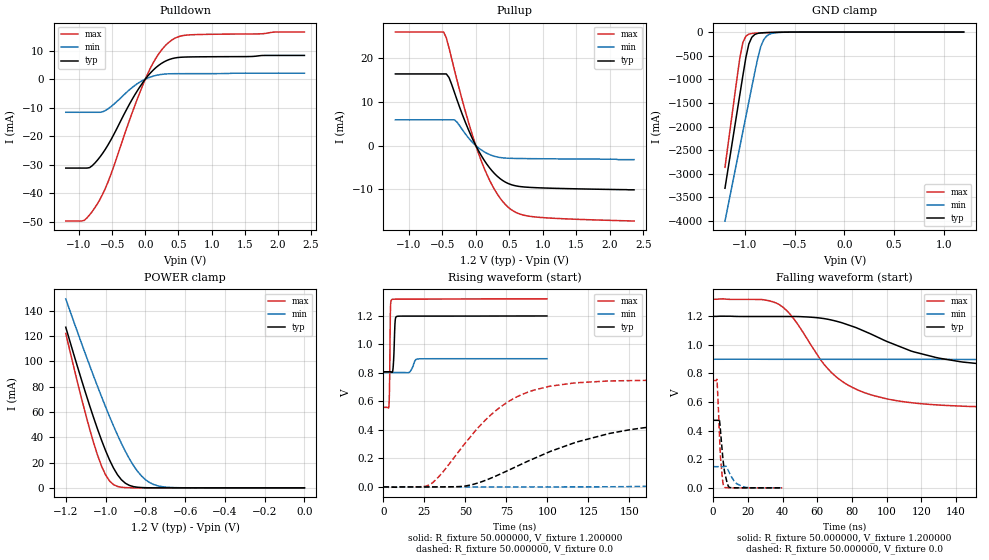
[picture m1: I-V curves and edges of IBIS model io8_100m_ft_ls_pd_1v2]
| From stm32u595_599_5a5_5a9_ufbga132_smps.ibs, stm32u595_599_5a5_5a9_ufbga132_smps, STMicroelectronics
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|   Model io8_100m_ft_ls_pd_1v2
[Model]  io8_100m_ft_ls_pd_1v2
Model_type I/O
Polarity   Non-Inverting
Enable   Active-Low
Vinl =   0.360000V
Vinh =   0.840000V
Vmeas =  0.600000V
Cref =   50.000000pF
Rref =   100.000000M
Vref =   0.0V
C_comp   2.947800pF   2.877700pF   2.996100pF
[Temperature Range]   25.000000   0.140000k   -40.000000
[Pullup Reference]   1.200000V   0.900000V   1.320000V
[Pulldown Reference]   0.0V   0.0V   0.0V
[POWER Clamp Reference]   1.200000V   0.900000V   1.320000V
[GND Clamp Reference]   0.0V   0.0V   0.0V
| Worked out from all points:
|   slope of the pulldown table from 0 to 0.18 V, typ, clamps not added: 40.7 ohm
|   slope of the pullup table from 0 to 0.18 V, typ, clamps not added: 39.5 ohm
|   GND clamp passes 1 mA (typ) near -0.51 V on its own axis
|   POWER clamp passes 1 mA (typ) near -0.86 V on its own axis
|   rising waveform, R_fixture 50.000000, V_fixture 1.200000: 20-80 % time 755ps typ, 2.06ns min, 442ps max; typ from 0.808 V to 1.2 V
|   rising waveform, R_fixture 50.000000, V_fixture 0.0: 20-80 % time 67.2ns typ, 166ns min, 37.1ns max; typ from 0 V to 0.472 V
|   falling waveform, R_fixture 50.000000, V_fixture 1.200000: 20-80 % time 58.2ns typ, 150ns min, 31.6ns max; typ from 1.2 V to 0.808 V
|   falling waveform, R_fixture 50.000000, V_fixture 0.0: 20-80 % time 2.49ns typ, 4.76ns min, 1.84ns max; typ from 0.472 V to 0 V
[Pulldown]
|Voltage   I(typ)   I(min)   I(max)
-1.2V     -31.16mA   -11.61mA   -49.71mA
-920mV    -31.16mA   -11.61mA   -49.48mA
-840mV    -31mA      -11.61mA   -47.54mA
-720mV    -28.33mA   -11.61mA   -43.58mA
-560mV    -22.95mA   -10.37mA   -35.89mA
-200mV    -7.146mA   -2.964mA   -11.89mA
0V        0A         0A         -10fA
160mV     4.047mA    1.298mA    7.361mA
360mV     6.87mA     1.87mA     13mA
480mV     7.543mA    1.91mA     14.69mA
640mV     7.765mA    1.923mA    15.46mA
2.4V      8.308mA    2.101mA    16.51mA
[Pullup]
|Voltage   I(typ)   I(min)   I(max)
-1.2V     16.39mA    5.9mA      25.96mA
-480mV    16.39mA    5.9mA      25.96mA
-440mV    16.39mA    5.9mA      24.63mA
-400mV    15.57mA    5.9mA      22.35mA
-320mV    12.21mA    5.9mA      17.37mA
-120mV    3.997mA    1.962mA    5.905mA
80mV      -2.237mA   -962.6uA   -3.434mA
280mV     -6.404mA   -2.453mA   -10.06mA
520mV     -8.88mA    -2.901mA   -14.54mA
680mV     -9.389mA   -2.951mA   -15.76mA
920mV     -9.627mA   -2.991mA   -16.35mA
2.36V     -10.1mA    -3.2mA     -17.23mA
[GND_clamp]
|Voltage   I(typ)   I(min)   I(max)
-1.2V     -3.305A    -3.998A    -2.862A
-1.05V    -1.316A    -2.418A    -539.3mA
-1.02V    -921mA     -2.103A    -218.8mA
-990mV    -539.5mA   -1.788A    -87.45mA
-960mV    -252.2mA   -1.474A    -44.37mA
-930mV    -110.5mA   -1.16A     -30.33mA
-870mV    -28.04mA   -549.1mA   -21.1mA
-840mV    -18.44mA   -305.6mA   -18.29mA
-810mV    -13.92mA   -159.7mA   -15.75mA
-780mV    -11.24mA   -82.36mA   -13.39mA
-600mV    -2.986mA   -4.279mA   -3.072mA
1.2V      30.28uA    18.17uA    37.27uA
[POWER_clamp]
|Voltage   I(typ)   I(min)   I(max)
-1.2V     127mA      149.4mA    122.2mA
-1.12V    84.97mA    114mA      70.27mA
-1.06V    55.51mA    88.42mA    35.67mA
-1.02V    37.63mA    72.04mA    17.17mA
-1V       29.51mA    64.13mA    10.3mA
-960mV    15.69mA    48.99mA    2.571mA
-900mV    3.624mA    28.77mA    182.8uA
-840mV    490.7uA    13.24mA    11.35uA
-800mV    116.8uA    6.532mA    1.77uA
-740mV    13.2uA     1.723mA    109.1nA
-620mV    167.3nA    79.35uA    0A
0V        0A         17.84nA    0A
[Ramp]
| variable   typ   min   max
dV/dt_r  0.28339/67.10641n   88.78788m/0.16576u  0.45041/37.04761n
dV/dt_f  0.23487/58.11029n   58.03200m/0.14982u  0.45672/31.53662n
R_load = 50.000000
[Rising Waveform]
R_fixture= 50.000000
V_fixture= 1.200000
V_fixture_min= 0.900000
V_fixture_max= 1.320000
|time   V(typ)   V(min)   V(max)
0s        808mV      802.7mV    558.2mV
3.403ns   808mV      802.7mV    574.6mV
3.804ns   808.1mV    802.7mV    764.5mV
4.204ns   808mV      802.7mV    1.211V
5.205ns   803.5mV    802.7mV    1.315V
6.006ns   851.7mV    802.7mV    1.317V
7.207ns   1.172V     802.7mV    1.317V
8.208ns   1.196V     802.7mV    1.317V
21.22ns   1.199V     898mV      1.318V
99.7ns    1.199V     899.4mV    1.319V
[Rising Waveform]
R_fixture= 50.000000
V_fixture= 0.0
V_fixture_min= 0.0
V_fixture_max= 0.0
|time   V(typ)   V(min)   V(max)
0s        2.199nV    207.3nV    1.402nV
28.03ns   -93.5uV    -27.23uV   14mV
50.05ns   6.453mV    -21.99uV   309mV
72.07ns   94.59mV    16.67uV    566.5mV
92.09ns   200.4mV    68.84uV    680.1mV
118.1ns   315.6mV    408.4uV    730.8mV
172.2ns   431.6mV    7.619mV    749.8mV
258.3ns   468.5mV    57.1mV     750.8mV
462.5ns   472.3mV    136.1mV    750.7mV
997ns     472.4mV    148.1mV    750.8mV
[Falling Waveform]
R_fixture= 50.000000
V_fixture= 1.200000
V_fixture_min= 0.900000
V_fixture_max= 1.320000
|time   V(typ)   V(min)   V(max)
0s        1.199V     899.4mV    1.319V
36.04ns   1.198V     899.1mV    1.294V
46.05ns   1.198V     899.1mV    1.189V
64.06ns   1.184V     899.1mV    861.5mV
76.08ns   1.147V     899.1mV    730.9mV
100.1ns   1.024V     899.1mV    622.2mV
132.1ns   903.2mV    898.6mV    577.6mV
172.2ns   845.4mV    895.4mV    562.8mV
278.3ns   811.5mV    849mV      558.1mV
997ns     808mV      802.7mV    558.2mV
[Falling Waveform]
R_fixture= 50.000000
V_fixture= 0.0
V_fixture_min= 0.0
V_fixture_max= 0.0
|time   V(typ)   V(min)   V(max)
0s        472.4mV    148.1mV    750.8mV
2.242ns   472.4mV    148.1mV    755.6mV
3.604ns   479.5mV    148.1mV    395.5mV
4.324ns   393.3mV    148.1mV    211.3mV
5.606ns   215.1mV    147.9mV    43.66mV
6.166ns   150.7mV    148.2mV    8.392mV
8.088ns   36.11mV    138.5mV    820.7uV
9.449ns   2.52mV     103.9mV    223.7uV
17.22ns   14.62uV    8.39mV     -46.01uV
39.88ns   2.199nV    207.3nV    1.402nV
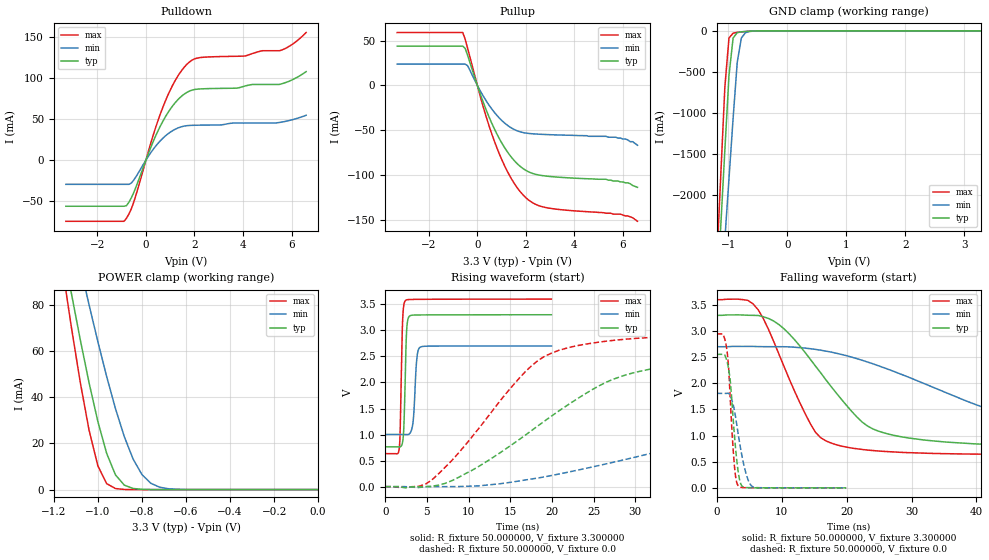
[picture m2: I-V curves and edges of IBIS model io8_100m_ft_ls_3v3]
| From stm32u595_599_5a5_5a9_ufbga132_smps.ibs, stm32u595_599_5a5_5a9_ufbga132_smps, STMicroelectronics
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|   Model io8_100m_ft_ls_3v3
[Model]  io8_100m_ft_ls_3v3
Model_type I/O
Polarity   Non-Inverting
Enable   Active-Low
Vinl =   0.990000V
Vinh =   2.310000V
Vmeas =  1.650000V
Cref =   50.000000pF
Rref =   100.000000M
Vref =   0.0V
C_comp   3.313100pF   3.281800pF   3.354500pF
[Temperature Range]   25.000000   0.140000k   -40.000000
[Pullup Reference]   3.300000V   2.700000V   3.600000V
[Pulldown Reference]   0.0V   0.0V   0.0V
[POWER Clamp Reference]   3.300000V   2.700000V   3.600000V
[GND Clamp Reference]   0.0V   0.0V   0.0V
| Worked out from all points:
|   slope of the pulldown table from 0 to 0.495 V, typ, clamps not added: 14 ohm
|   slope of the pullup table from 0 to 0.495 V, typ, clamps not added: 13.7 ohm
|   GND clamp passes 1 mA (typ) near -0.51 V on its own axis
|   POWER clamp passes 1 mA (typ) near -0.85 V on its own axis
|   rising waveform, R_fixture 50.000000, V_fixture 3.300000: 20-80 % time 251ps typ, 341ps min, 235ps max; typ from 0.764 V to 3.3 V
|   rising waveform, R_fixture 50.000000, V_fixture 0.0: 20-80 % time 14.6ns typ, 31.2ns min, 9.34ns max; typ from 0 V to 2.55 V
|   falling waveform, R_fixture 50.000000, V_fixture 3.300000: 20-80 % time 10ns typ, 23.1ns min, 6.36ns max; typ from 3.3 V to 0.764 V
|   falling waveform, R_fixture 50.000000, V_fixture 0.0: 20-80 % time 1.02ns typ, 1.54ns min, 818ps max; typ from 2.55 V to 0 V
[Pulldown]
|Voltage   I(typ)   I(min)   I(max)
-3.3V     -56.06mA   -29.42mA   -74.35mA
-900mV    -56.06mA   -29.42mA   -74.35mA
-700mV    -51.09mA   -29.42mA   -65.48mA
-500mV    -39.32mA   -24.2mA    -50.88mA
300mV     22.62mA    13.13mA    30.43mA
800mV     52.54mA    29.36mA    71.75mA
1.3V      72.91mA    38.82mA    101.4mA
1.8V      84.02mA    42.13mA    119.4mA
2.2V      86.43mA    42.46mA    124.5mA
5.5V      91.98mA    45.75mA    132.9mA
6.1V      98.6mA     49.6mA     142.1mA
6.6V      107.5mA    54.5mA     155mA
[Pullup]
|Voltage   I(typ)   I(min)   I(max)
-3.3V     43.8mA     23.73mA    58.97mA
-600mV    43.8mA     23.73mA    58.97mA
-500mV    41.28mA    23.73mA    51.53mA
-400mV    33.57mA    21.9mA     41.51mA
300mV     -22.93mA   -14.5mA    -29.27mA
800mV     -54.04mA   -33.36mA   -69.41mA
1.4V      -80.24mA   -47.59mA   -104.2mA
2.1V      -96.56mA   -53.74mA   -127.9mA
3V        -101.9mA   -55.18mA   -137.5mA
5.7V      -107mA     -58mA      -144mA
6.2V      -109mA     -61mA      -146mA
6.6V      -114mA     -67mA      -152mA
[GND_clamp]
|Voltage   I(typ)   I(min)   I(max)
-3.3V     -9.848A    -9.957A    -9.458A
-1.2V     -3.312A    -4.013A    -2.863A
-1.13V    -2.381A    -3.274A    -1.769A
-1.06V    -1.452A    -2.535A    -684.7mA
-990mV    -542.9mA   -1.798A    -88.02mA
-920mV    -87.11mA   -1.064A    -28.44mA
-850mV    -22.1mA    -382.4mA   -19.61mA
-780mV    -11.97mA   -86.98mA   -13.71mA
-710mV    -7.619mA   -22.26mA   -8.745mA
-640mV    -4.493mA   -7.773mA   -4.817mA
-360mV    -31.22uA   -172.6uA   -8.607uA
3.28V     0A         15.66nA    -5.841nA
[POWER_clamp]
|Voltage   I(typ)   I(min)   I(max)
-3.28V    1.355A     1.167A     1.664A
-1.16V    105.7mA    131.6mA    95.69mA
-1.12V    84.97mA    114mA      70.27mA
-1.08V    65.05mA    96.83mA    46.54mA
-1.04V    46.34mA    80.15mA    25.76mA
-1V       29.51mA    64.13mA    10.3mA
-960mV    15.69mA    48.99mA    2.571mA
-920mV    6.373mA    35.1mA     455.6uA
-840mV    490.7uA    13.24mA    11.36uA
-760mV    27.33uA    2.767mA    276.6nA
-640mV    346.6nA    134.1uA    15.62nA
0V        0A         19.91nA    0A
[Ramp]
| variable   typ   min   max
dV/dt_r  1.53252/14.60637n   1.08432/31.19621n   1.76664/9.31314n
dV/dt_f  1.52148/10.00275n   1.01892/23.07140n   1.77963/6.34628n
R_load = 50.000000
[Rising Waveform]
R_fixture= 50.000000
V_fixture= 3.300000
V_fixture_min= 2.700000
V_fixture_max= 3.600000
|time   V(typ)   V(min)   V(max)
0s        764.2mV    1.002V     633.9mV
1.682ns   762.3mV    1.002V     731.5mV
2.082ns   853.1mV    1.002V     3.162V
2.242ns   1.17V      1.002V     3.495V
2.442ns   2.344V     1.001V     3.574V
2.763ns   3.234V     1.002V     3.591V
3.323ns   3.293V     1.218V     3.594V
3.804ns   3.295V     2.474V     3.595V
4.204ns   3.296V     2.678V     3.596V
19.94ns   3.3V       2.7V       3.6V
[Rising Waveform]
R_fixture= 50.000000
V_fixture= 0.0
V_fixture_min= 0.0
V_fixture_max= 0.0
|time   V(typ)   V(min)   V(max)
0s        17.53nV    119.4nV    55.53nV
5.606ns   7.05mV     -448.8uV   129.3mV
11.21ns   387.1mV    14.87mV    1.114V
16.02ns   897.2mV    107.3mV    2.069V
19.22ns   1.271V     190.9mV    2.51V
27.23ns   2.054V     462.9mV    2.806V
34.43ns   2.325V     738.3mV    2.884V
59.26ns   2.523V     1.516V     2.94V
94.49ns   2.552V     1.752V     2.944V
398.8ns   2.554V     1.807V     2.944V
[Falling Waveform]
R_fixture= 50.000000
V_fixture= 3.300000
V_fixture_min= 2.700000
V_fixture_max= 3.600000
|time   V(typ)   V(min)   V(max)
0s        3.3V       2.7V       3.6V
4.805ns   3.302V     2.706V     3.587V
6.406ns   3.297V     2.703V     3.405V
10.41ns   3.038V     2.7V       2.312V
16.02ns   2.202V     2.634V     959.3mV
21.62ns   1.352V     2.471V     747.5mV
25.63ns   1.057V     2.304V     698.7mV
46.45ns   810.2mV    1.363V     640mV
76.08ns   770.8mV    1.088V     634.4mV
398.8ns   764.2mV    1.002V     633.9mV
[Falling Waveform]
R_fixture= 50.000000
V_fixture= 0.0
V_fixture_min= 0.0
V_fixture_max= 0.0
|time   V(typ)   V(min)   V(max)
0s        2.554V     1.807V     2.944V
920.9ps   2.554V     1.807V     2.944V
1.562ns   2.438V     1.808V     2.66V
1.842ns   2.279V     1.81V      2.314V
2.082ns   2.072V     1.763V     1.755V
2.683ns   1.102V     1.521V     512.9mV
3.323ns   311.1mV    1.033V     39.72mV
4.525ns   5.998mV    276.9mV    3.705mV
5.606ns   2.233mV    17.3mV     2.761mV
19.94ns   17.53nV    119.4nV    55.53nV
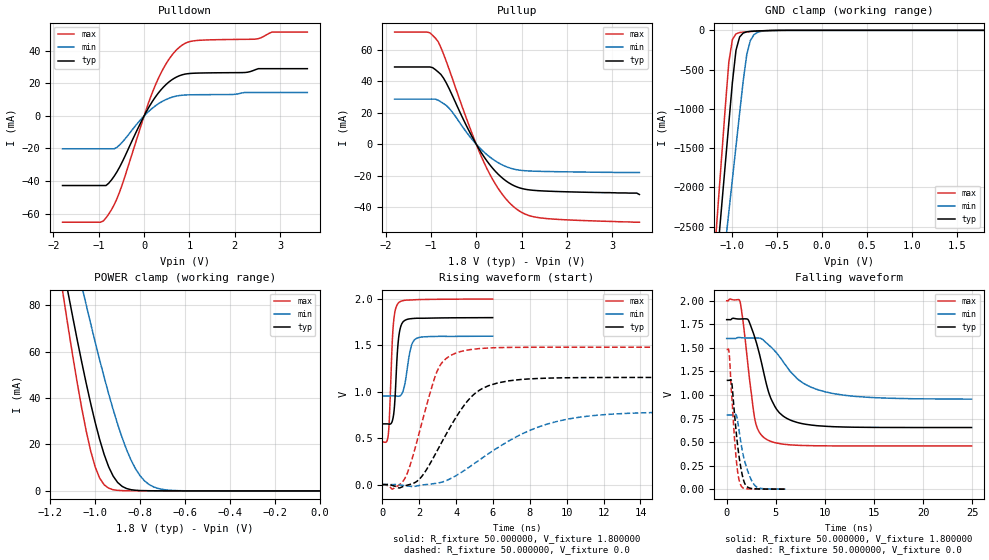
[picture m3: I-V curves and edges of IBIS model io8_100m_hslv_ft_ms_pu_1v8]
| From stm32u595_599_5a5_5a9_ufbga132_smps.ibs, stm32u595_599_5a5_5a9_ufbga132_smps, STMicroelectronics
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|   Model io8_100m_hslv_ft_ms_pu_1v8
[Model]  io8_100m_hslv_ft_ms_pu_1v8
Model_type I/O
Polarity   Non-Inverting
Enable   Active-Low
Vinl =   0.540000V
Vinh =   1.260000V
Vmeas =  0.900000V
Cref =   50.000000pF
Rref =   100.000000M
Vref =   0.0V
C_comp   3.235100pF   3.233200pF   3.282800pF
[Temperature Range]   25.000000   0.140000k   -40.000000
[Pullup Reference]   1.800000V   1.600000V   2.000000V
[Pulldown Reference]   0.0V   0.0V   0.0V
[POWER Clamp Reference]   1.800000V   1.600000V   2.000000V
[GND Clamp Reference]   0.0V   0.0V   0.0V
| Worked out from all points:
|   slope of the pulldown table from 0 to 0.27 V, typ, clamps not added: 21.7 ohm
|   slope of the pullup table from 0 to 0.27 V, typ, clamps not added: 22.6 ohm
|   GND clamp passes 1 mA (typ) near -0.51 V on its own axis
|   POWER clamp passes 1 mA (typ) near -0.86 V on its own axis
|   rising waveform, R_fixture 50.000000, V_fixture 1.800000: 20-80 % time 206ps typ, 322ps min, 192ps max; typ from 0.655 V to 1.8 V
|   rising waveform, R_fixture 50.000000, V_fixture 0.0: 20-80 % time 2.12ns typ, 4.11ns min, 1.26ns max; typ from 0.001 V to 1.16 V
|   falling waveform, R_fixture 50.000000, V_fixture 1.800000: 20-80 % time 1.9ns typ, 3.69ns min, 1.06ns max; typ from 1.8 V to 0.655 V
|   falling waveform, R_fixture 50.000000, V_fixture 0.0: 20-80 % time 745ps typ, 1.02ns min, 591ps max; typ from 1.16 V to 0.001 V
[Pulldown]
|Voltage   I(typ)   I(min)   I(max)
-1.8V     -42.74mA   -20.21mA   -65.25mA
-960mV    -42.74mA   -20.21mA   -65.25mA
-780mV    -41.3mA    -20.21mA   -60.25mA
-540mV    -31.39mA   -17.82mA   -46.65mA
0V        0A         0A         0A
240mV     11.28mA    6.002mA    18.38mA
480mV     19.17mA    10.02mA    31.83mA
780mV     24.67mA    12.5mA     42.21mA
1.14V     26.24mA    12.99mA    46.23mA
2.46V     28.42mA    14.38mA    47.14mA
2.82V     28.99mA    14.38mA    51.44mA
3.6V      28.99mA    14.38mA    51.44mA
[Pullup]
|Voltage   I(typ)   I(min)   I(max)
-1.8V     49.08mA    28.63mA    71.26mA
-1.08V    49.08mA    28.63mA    71.26mA
-840mV    45.94mA    27.95mA    65.24mA
-720mV    41.96mA    25.82mA    57.24mA
-600mV    35.46mA    22.92mA    47.84mA
-180mV    9.685mA    6.268mA    13.58mA
180mV     -8.368mA   -5.234mA   -12.14mA
540mV     -20.62mA   -12.68mA   -30.5mA
900mV     -27.22mA   -16.28mA   -41.49mA
1.14V     -28.94mA   -17mA      -45.14mA
1.5V      -29.77mA   -17.34mA   -47.14mA
3.6V      -32mA      -18mA      -49.6mA
[GND_clamp]
|Voltage   I(typ)   I(min)   I(max)
-1.8V     -9.707A    -9.942A    -9.774A
-1.2V     -3.309A    -4.006A    -2.864A
-1.16V    -2.777A    -3.584A    -2.239A
-1.12V    -2.246A    -3.162A    -1.614A
-1.04V    -1.186A    -2.319A    -408.6mA
-1V       -663.9mA   -1.898A    -117.8mA
-960mV    -254mA     -1.478A    -45.14mA
-920mV    -86.03mA   -1.06A     -28.58mA
-840mV    -19.12mA   -308.9mA   -18.74mA
-800mV    -13.39mA   -130.8mA   -15.31mA
-720mV    -7.948mA   -25.37mA   -9.381mA
1.8V      0A         14.95nA    0A
[POWER_clamp]
|Voltage   I(typ)   I(min)   I(max)
-1.8V     470.9mA    433.7mA    554.6mA
-1.14V    95.28mA    122.7mA    82.88mA
-1.12V    85mA       114mA      70.34mA
-1.06V    55.55mA    88.43mA    35.73mA
-1.04V    46.38mA    80.17mA    25.83mA
-1V       29.54mA    64.14mA    10.37mA
-940mV    10.43mA    41.88mA    1.177mA
-900mV    3.66mA     28.79mA    250.5uA
-840mV    527.2uA    13.26mA    94.87uA
-800mV    153.8uA    6.55mA     88.76uA
-740mV    60.08uA    1.741mA    70.81uA
0V        0A         18.15nA    0A
[Ramp]
| variable   typ   min   max
dV/dt_r  0.69287/2.11680n   0.47199/4.10950n   0.88855/1.25761n
dV/dt_f  0.68716/1.89749n   0.38583/3.69003n   0.92438/1.05316n
R_load = 50.000000
[Rising Waveform]
R_fixture= 50.000000
V_fixture= 1.800000
V_fixture_min= 1.600000
V_fixture_max= 2.000000
|time   V(typ)   V(min)   V(max)
0s        654.8mV    956.1mV    459.4mV
324.3ps   653.5mV    956.2mV    543.8mV
384.4ps   651.6mV    956.3mV    735.2mV
588.6ps   727.3mV    956.3mV    1.707V
684.7ps   925.5mV    955.9mV    1.866V
852.9ps   1.524V     952.6mV    1.953V
1.093ns   1.747V     993.5mV    1.982V
1.562ns   1.789V     1.488V     1.99V
1.826ns   1.793V     1.573V     1.993V
5.982ns   1.8V       1.6V       2V
[Rising Waveform]
R_fixture= 50.000000
V_fixture= 0.0
V_fixture_min= 0.0
V_fixture_max= 0.0
|time   V(typ)   V(min)   V(max)
0s        521.2uV    669.3uV    497.7uV
550.6ps   -9.762mV   627.1uV    -49.01mV
1.201ns   -14.47mV   -10.34mV   60.59mV
2.052ns   68.27mV    -7.349mV   598.4mV
2.953ns   358mV      15mV       1.214V
4.154ns   774.7mV    116.1mV    1.429V
5.756ns   1.066V     332.9mV    1.472V
7.908ns   1.139V     576.7mV    1.48V
10.16ns   1.152V     710mV      1.481V
24.92ns   1.156V     787.5mV    1.481V
[Falling Waveform]
R_fixture= 50.000000
V_fixture= 1.800000
V_fixture_min= 1.600000
V_fixture_max= 2.000000
|time   V(typ)   V(min)   V(max)
0s        1.8V       1.6V       2V
1.351ns   1.807V     1.61V      1.994V
2.152ns   1.803V     1.604V     1.331V
2.853ns   1.613V     1.605V     750.5mV
4.054ns   1.112V     1.552V     529.3mV
4.905ns   878.6mV    1.467V     494.6mV
5.706ns   779.9mV    1.36V      478.5mV
7.257ns   706.5mV    1.166V     466.2mV
10.11ns   667.7mV    1.032V     460.4mV
24.92ns   654.8mV    956.1mV    459.4mV
[Falling Waveform]
R_fixture= 50.000000
V_fixture= 0.0
V_fixture_min= 0.0
V_fixture_max= 0.0
|time   V(typ)   V(min)   V(max)
0s        1.156V     787.5mV    1.481V
240.2ps   1.155V     787.6mV    1.453V
492.5ps   1.145V     787.7mV    1.019V
768.8ps   830.7mV    790.7mV    579.6mV
997ps     575.8mV    781.9mV    292.7mV
1.189ns   402.6mV    674.7mV    135.4mV
1.405ns   250.7mV    521.8mV    50.3mV
1.886ns   51.07mV    278.1mV    5.84mV
2.811ns   4.631mV    46.35mV    1.986mV
5.982ns   521.2uV    669.3uV    497.7uV
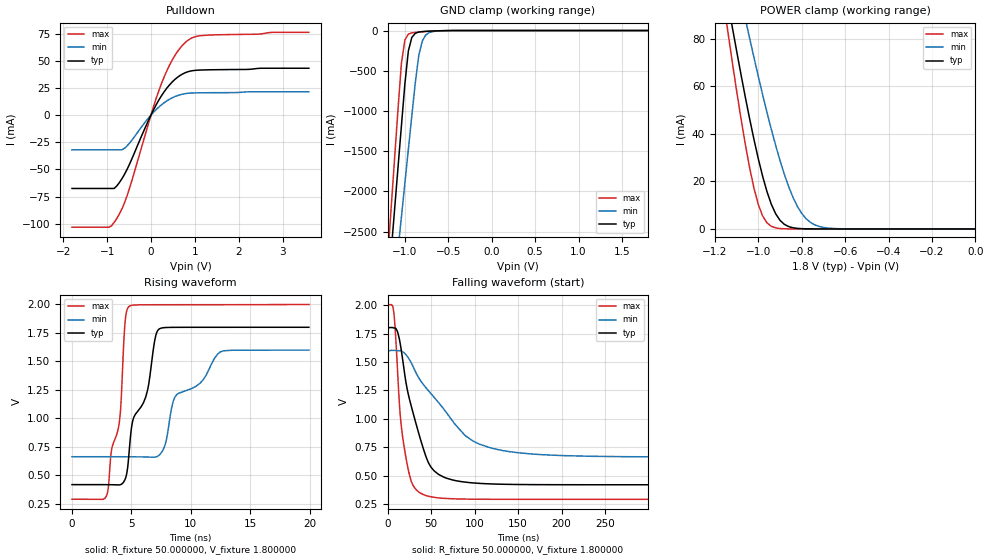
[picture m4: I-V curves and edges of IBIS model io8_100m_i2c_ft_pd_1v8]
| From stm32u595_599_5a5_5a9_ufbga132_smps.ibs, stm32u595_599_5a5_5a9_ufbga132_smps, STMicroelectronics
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|   Model io8_100m_i2c_ft_pd_1v8
[Model]  io8_100m_i2c_ft_pd_1v8
Model_type I/O_open_drain
Polarity   Non-Inverting
Enable   Active-Low
Vinl =   0.540000V
Vinh =   1.260000V
Vmeas =  0.900000V
Cref =   50.000000pF
Rref =   10.000000k
Vref =   1.800000V
C_comp   3.154800pF   3.154000pF   3.203200pF
[Temperature Range]   25.000000   0.140000k   -40.000000
[Pullup Reference]   1.800000V   1.600000V   2.000000V
[Pulldown Reference]   0.0V   0.0V   0.0V
[POWER Clamp Reference]   1.800000V   1.600000V   2.000000V
[GND Clamp Reference]   0.0V   0.0V   0.0V
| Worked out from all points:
|   slope of the pulldown table from 0 to 0.27 V, typ, clamps not added: 13.8 ohm
|   GND clamp passes 1 mA (typ) near -0.51 V on its own axis
|   POWER clamp passes 1 mA (typ) near -0.86 V on its own axis
|   rising waveform, R_fixture 50.000000, V_fixture 1.800000: 20-80 % time 1.94ns typ, 3.43ns min, 1.12ns max; typ from 0.419 V to 1.8 V
|   falling waveform, R_fixture 50.000000, V_fixture 1.800000: 20-80 % time 25.6ns typ, 57.3ns min, 11.9ns max; typ from 1.8 V to 0.419 V
[Pulldown]
|Voltage   I(typ)   I(min)   I(max)
-1.8V     -67.53mA   -31.92mA   -103.2mA
-960mV    -67.53mA   -31.92mA   -103.2mA
-840mV    -67.53mA   -31.92mA   -98.87mA
-780mV    -65.26mA   -31.92mA   -95.24mA
-660mV    -58.47mA   -31.92mA   -86.15mA
-540mV    -49.6mA    -28.16mA   -73.74mA
0V        0A         0A         0A
240mV     17.82mA    9.483mA    29.05mA
540mV     32.64mA    16.95mA    54.49mA
840mV     39.89mA    20.07mA    68.75mA
1.2V      41.57mA    20.56mA    73.35mA
3.6V      43.14mA    21.43mA    76.19mA
[GND_clamp]
|Voltage   I(typ)   I(min)   I(max)
-1.8V     -9.707A    -9.942A    -9.774A
-1.2V     -3.309A    -4.006A    -2.865A
-1.16V    -2.777A    -3.584A    -2.239A
-1.12V    -2.246A    -3.162A    -1.614A
-1.04V    -1.186A    -2.319A    -408.7mA
-1V       -663.9mA   -1.898A    -117.8mA
-960mV    -254mA     -1.478A    -45.15mA
-920mV    -86.04mA   -1.06A     -28.6mA
-840mV    -19.13mA   -308.9mA   -18.75mA
-800mV    -13.4mA    -130.8mA   -15.33mA
-720mV    -7.959mA   -25.38mA   -9.395mA
1.8V      45.71uA    33.33uA    56.11uA
[POWER_clamp]
|Voltage   I(typ)   I(min)   I(max)
-1.8V     470.8mA    433.7mA    554.6mA
-1.14V    95.25mA    122.7mA    82.82mA
-1.12V    84.97mA    114mA      70.27mA
-1.06V    55.51mA    88.42mA    35.67mA
-1.04V    46.34mA    80.15mA    25.76mA
-1V       29.51mA    64.13mA    10.3mA
-940mV    10.39mA    41.86mA    1.109mA
-900mV    3.624mA    28.77mA    182.8uA
-840mV    490.7uA    13.24mA    11.35uA
-800mV    116.8uA    6.532mA    1.77uA
-740mV    13.2uA     1.723mA    109.3nA
0V        0A         18.72nA    0A
[Ramp]
| variable   typ   min   max
dV/dt_r  0.82816/1.94110n   0.56104/3.43302n   1.02518/1.12128n
dV/dt_f  0.82834/25.55606n   0.56138/57.21737n   1.02518/11.91880n
R_load = 50.000000
[Rising Waveform]
R_fixture= 50.000000
V_fixture= 1.800000
V_fixture_min= 1.600000
V_fixture_max= 2.000000
|time   V(typ)   V(min)   V(max)
0s        418.8mV    663.5mV    290.7mV
2.963ns   418.3mV    663.5mV    337.2mV
3.323ns   418mV      663.5mV    719.5mV
4.004ns   416.9mV    663.5mV    982.4mV
4.444ns   459.5mV    663.3mV    1.815V
4.805ns   700.8mV    663mV      1.982V
7.327ns   1.783V     676.4mV    1.997V
8.689ns   1.799V     1.192V     1.997V
12.49ns   1.799V     1.584V     1.997V
19.94ns   1.799V     1.599V     1.999V
[Falling Waveform]
R_fixture= 50.000000
V_fixture= 1.800000
V_fixture_min= 1.600000
V_fixture_max= 2.000000
|time   V(typ)   V(min)   V(max)
0s        1.799V     1.599V     1.999V
7.207ns   1.799V     1.601V     1.939V
14.41ns   1.669V     1.598V     1.051V
20.82ns   1.338V     1.568V     674mV
27.23ns   1.113V     1.492V     449.9mV
38.44ns   805mV      1.33V      342.8mV
58.46ns   511.4mV    1.144V     303.5mV
88.89ns   442.5mV    855.1mV    292.8mV
119.3ns   426.2mV    741.7mV    291mV
398.8ns   418.8mV    663.5mV    290.7mV
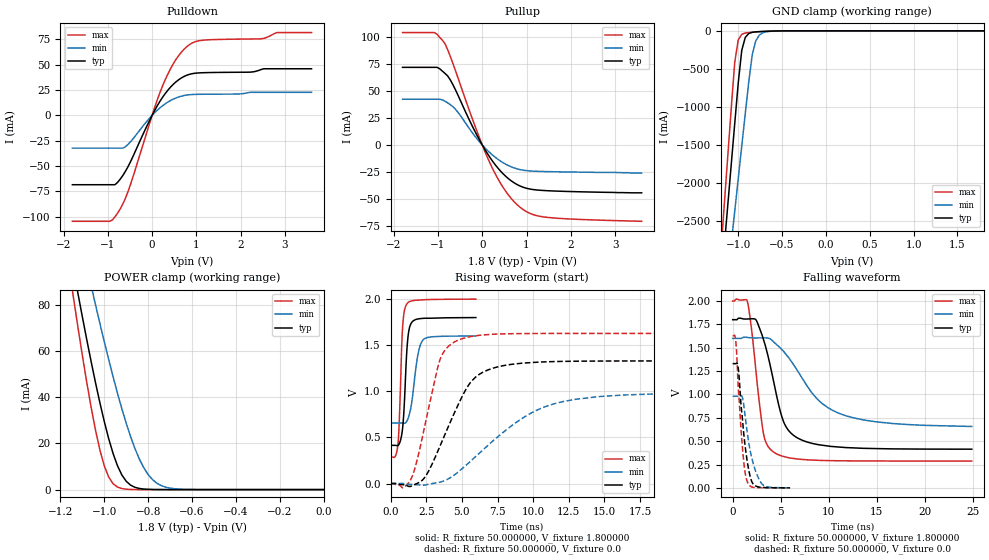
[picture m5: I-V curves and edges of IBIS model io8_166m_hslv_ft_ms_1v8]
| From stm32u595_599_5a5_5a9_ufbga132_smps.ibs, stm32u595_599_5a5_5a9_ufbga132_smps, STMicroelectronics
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|   Model io8_166m_hslv_ft_ms_1v8
[Model]  io8_166m_hslv_ft_ms_1v8
Model_type I/O
Polarity   Non-Inverting
Enable   Active-Low
Vinl =   0.540000V
Vinh =   1.260000V
Vmeas =  0.900000V
Cref =   50.000000pF
Rref =   100.000000M
Vref =   0.0V
C_comp   3.358400pF   3.352800pF   3.400400pF
[Temperature Range]   25.000000   0.140000k   -40.000000
[Pullup Reference]   1.800000V   1.600000V   2.000000V
[Pulldown Reference]   0.0V   0.0V   0.0V
[POWER Clamp Reference]   1.800000V   1.600000V   2.000000V
[GND Clamp Reference]   0.0V   0.0V   0.0V
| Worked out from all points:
|   slope of the pulldown table from 0 to 0.27 V, typ, clamps not added: 13.6 ohm
|   slope of the pullup table from 0 to 0.27 V, typ, clamps not added: 15.9 ohm
|   GND clamp passes 1 mA (typ) near -0.51 V on its own axis
|   POWER clamp passes 1 mA (typ) near -0.86 V on its own axis
|   rising waveform, R_fixture 50.000000, V_fixture 1.800000: 20-80 % time 285ps typ, 490ps min, 232ps max; typ from 0.414 V to 1.8 V
|   rising waveform, R_fixture 50.000000, V_fixture 0.0: 20-80 % time 2.38ns typ, 4.83ns min, 1.41ns max; typ from 0 V to 1.33 V
|   falling waveform, R_fixture 50.000000, V_fixture 1.800000: 20-80 % time 1.98ns typ, 4.45ns min, 1.12ns max; typ from 1.8 V to 0.414 V
|   falling waveform, R_fixture 50.000000, V_fixture 0.0: 20-80 % time 794ps typ, 1.05ns min, 630ps max; typ from 1.33 V to 0 V
[Pulldown]
|Voltage   I(typ)   I(min)   I(max)
-1.8V     -68.38mA   -32.32mA   -104.4mA
-960mV    -68.38mA   -32.32mA   -104.4mA
-780mV    -66.08mA   -32.32mA   -96.42mA
-540mV    -50.22mA   -28.51mA   -74.66mA
0V        0A         -400fA     0A
240mV     18.04mA    9.6mA      29.42mA
480mV     30.68mA    16.02mA    50.95mA
780mV     39.48mA    19.99mA    67.57mA
1.14V     41.99mA    20.78mA    74.01mA
2.46V     45.09mA    22.69mA    75.45mA
2.82V     45.91mA    22.69mA    81.58mA
3.6V      45.91mA    22.69mA    81.58mA
[Pullup]
|Voltage   I(typ)   I(min)   I(max)
-1.8V     71.67mA    42.21mA    103.8mA
-1.08V    71.67mA    42.21mA    103.8mA
-840mV    66.04mA    40.35mA    93.41mA
-720mV    60.01mA    37.18mA    81.6mA
-600mV    50.51mA    32.72mA    68.09mA
-180mV    13.77mA    8.913mA    19.32mA
180mV     -11.9mA    -7.442mA   -17.26mA
480mV     -26.98mA   -16.65mA   -39.76mA
840mV     -37.65mA   -22.63mA   -57.07mA
1.08V     -40.74mA   -24.01mA   -63.22mA
1.44V     -42.19mA   -24.58mA   -66.73mA
3.6V      -44.2mA    -26mA      -70.5mA
[GND_clamp]
|Voltage   I(typ)   I(min)   I(max)
-1.8V     -9.908A    -9.683A    -9.994A
-1.2V     -3.383A    -4.084A    -2.934A
-1.16V    -2.841A    -3.655A    -2.294A
-1.12V    -2.299A    -3.226A    -1.656A
-1.04V    -1.218A    -2.369A    -414.2mA
-1V       -684.7mA   -1.941A    -119.2mA
-960mV    -257.2mA   -1.514A    -45.66mA
-920mV    -87.03mA   -1.089A    -28.93mA
-840mV    -19.35mA   -312.8mA   -18.97mA
-800mV    -13.55mA   -132.4mA   -15.49mA
-720mV    -8.042mA   -25.67mA   -9.491mA
1.8V      0A         13.64nA    0A
[POWER_clamp]
|Voltage   I(typ)   I(min)   I(max)
-1.8V     470.8mA    433.7mA    554.6mA
-1.14V    95.25mA    122.7mA    82.82mA
-1.12V    84.97mA    114mA      70.27mA
-1.06V    55.51mA    88.42mA    35.67mA
-1.04V    46.34mA    80.15mA    25.76mA
-1V       29.51mA    64.13mA    10.3mA
-940mV    10.39mA    41.86mA    1.109mA
-900mV    3.624mA    28.77mA    182.8uA
-840mV    490.7uA    13.24mA    11.35uA
-800mV    116.8uA    6.532mA    1.77uA
-740mV    13.2uA     1.724mA    109.3nA
0V        0A         18.75nA    0A
[Ramp]
| variable   typ   min   max
dV/dt_r  0.79770/2.37724n   0.58715/4.82437n   0.97662/1.40803n
dV/dt_f  0.83153/1.97182n   0.56146/4.43655n   1.02770/1.11781n
R_load = 50.000000
[Rising Waveform]
R_fixture= 50.000000
V_fixture= 1.800000
V_fixture_min= 1.600000
V_fixture_max= 2.000000
|time   V(typ)   V(min)   V(max)
0s        413.9mV    656.9mV    287.2mV
516.5ps   412.3mV    657mV      425mV
612.6ps   432.3mV    657mV      689.1mV
840.8ps   596mV      655.5mV    1.687V
1.105ns   1.345V     667.3mV    1.939V
1.213ns   1.578V     700.3mV    1.961V
1.369ns   1.712V     783.3mV    1.976V
1.886ns   1.784V     1.369V     1.988V
2.246ns   1.791V     1.552V     1.992V
5.982ns   1.8V       1.6V       2V
[Rising Waveform]
R_fixture= 50.000000
V_fixture= 0.0
V_fixture_min= 0.0
V_fixture_max= 0.0
|time   V(typ)   V(min)   V(max)
0s        -16.28uV   -2.041uV   -26.58uV
850.9ps   -12.33mV   244.6uV    -47.07mV
1.451ns   -27.91mV   -9.694mV   54.62mV
2.352ns   57.35mV    -17.03mV   591mV
3.453ns   401.2mV    15.03mV    1.338V
4.705ns   842.9mV    120.4mV    1.553V
5.656ns   1.106V     248.8mV    1.595V
6.757ns   1.227V     403.8mV    1.614V
11.56ns   1.323V     868.6mV    1.628V
24.92ns   1.33V      980.3mV    1.628V
[Falling Waveform]
R_fixture= 50.000000
V_fixture= 1.800000
V_fixture_min= 1.600000
V_fixture_max= 2.000000
|time   V(typ)   V(min)   V(max)
0s        1.8V       1.6V       2V
1.552ns   1.808V     1.61V      1.989V
2.452ns   1.796V     1.605V     1.224V
3.203ns   1.591V     1.606V     587mV
4.304ns   1.122V     1.559V     380mV
5.556ns   655.2mV    1.429V     329.7mV
7.708ns   492.4mV    1.099V     300.5mV
9.96ns    447.7mV    856.3mV    291.9mV
12.56ns   427.9mV    750.5mV    288.6mV
24.92ns   413.9mV    656.9mV    287.2mV
[Falling Waveform]
R_fixture= 50.000000
V_fixture= 0.0
V_fixture_min= 0.0
V_fixture_max= 0.0
|time   V(typ)   V(min)   V(max)
0s        1.33V      980.3mV    1.628V
324.3ps   1.33V      980.4mV    1.568V
420.4ps   1.334V     980.5mV    1.438V
552.6ps   1.302V     980.5mV    1.136V
1.093ns   650.7mV    931mV      345.5mV
1.297ns   449.8mV    773.7mV    163.8mV
1.526ns   281.2mV    590.3mV    66.53mV
2.078ns   50.28mV    284.3mV    7.156mV
3.027ns   5.268mV    46.05mV    1.36mV
5.982ns   -16.28uV   -2.041uV   -26.58uV
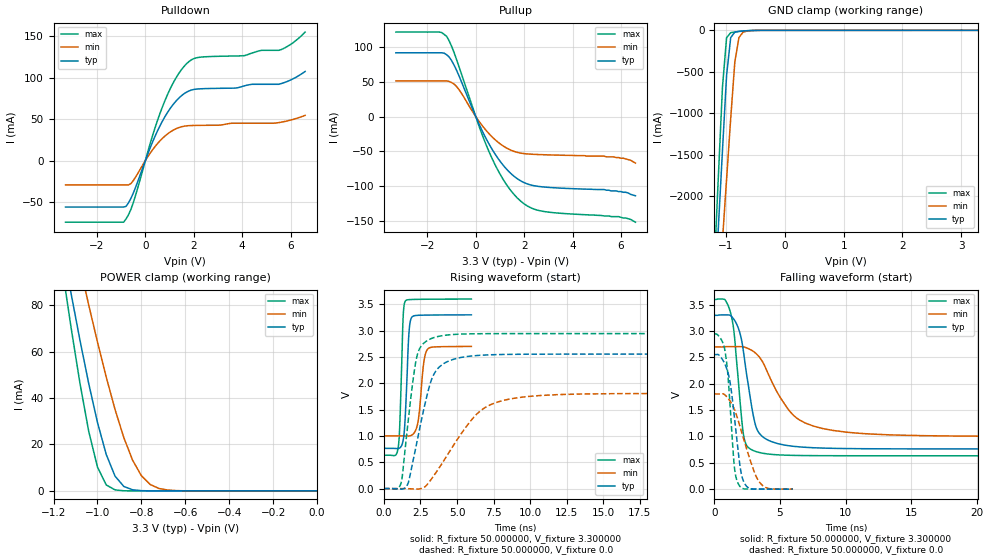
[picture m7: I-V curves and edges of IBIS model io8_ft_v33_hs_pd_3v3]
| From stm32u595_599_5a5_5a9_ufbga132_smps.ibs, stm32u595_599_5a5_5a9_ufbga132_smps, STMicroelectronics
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|   Model io8_ft_v33_hs_pd_3v3
[Model]  io8_ft_v33_hs_pd_3v3
Model_type I/O
Polarity   Non-Inverting
Enable   Active-Low
Vinl =   0.990000V
Vinh =   2.310000V
Vmeas =  1.650000V
Cref =   50.000000pF
Rref =   100.000000M
Vref =   0.0V
C_comp   3.252200pF   3.221000pF   3.293600pF
[Temperature Range]   25.000000   0.140000k   -40.000000
[Pullup Reference]   3.300000V   2.700000V   3.600000V
[Pulldown Reference]   0.0V   0.0V   0.0V
[POWER Clamp Reference]   3.300000V   2.700000V   3.600000V
[GND Clamp Reference]   0.0V   0.0V   0.0V
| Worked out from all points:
|   slope of the pulldown table from 0 to 0.495 V, typ, clamps not added: 14 ohm
|   slope of the pullup table from 0 to 0.495 V, typ, clamps not added: 13.7 ohm
|   GND clamp passes 1 mA (typ) near -0.50 V on its own axis
|   POWER clamp passes 1 mA (typ) near -0.85 V on its own axis
|   rising waveform, R_fixture 50.000000, V_fixture 3.300000: 20-80 % time 237ps typ, 338ps min, 194ps max; typ from 0.764 V to 3.3 V
|   rising waveform, R_fixture 50.000000, V_fixture 0.0: 20-80 % time 1.24ns typ, 2.77ns min, 756ps max; typ from 0 V to 2.55 V
|   falling waveform, R_fixture 50.000000, V_fixture 3.300000: 20-80 % time 973ps typ, 2.53ns min, 636ps max; typ from 3.3 V to 0.764 V
|   falling waveform, R_fixture 50.000000, V_fixture 0.0: 20-80 % time 731ps typ, 1.36ns min, 509ps max; typ from 2.55 V to 0 V
[Pulldown]
|Voltage   I(typ)   I(min)   I(max)
-3.3V     -56.06mA   -29.42mA   -74.35mA
-900mV    -56.06mA   -29.42mA   -74.35mA
-700mV    -51.09mA   -29.42mA   -65.48mA
-500mV    -39.32mA   -24.2mA    -50.88mA
300mV     22.62mA    13.13mA    30.42mA
800mV     52.54mA    29.36mA    71.75mA
1.3V      72.91mA    38.82mA    101.4mA
1.8V      84.02mA    42.13mA    119.4mA
2.2V      86.43mA    42.46mA    124.5mA
5.5V      92.01mA    45.75mA    133mA
6.1V      98.6mA     49.6mA     142.1mA
6.6V      107.5mA    54.5mA     155mA
[Pullup]
|Voltage   I(typ)   I(min)   I(max)
-3.3V     91.69mA    51.24mA    121.4mA
-1.5V     91.69mA    51.24mA    121.4mA
-1.2V     88.75mA    51.24mA    115.3mA
-800mV    67.17mA    43.46mA    82.71mA
100mV     -8.009mA   -5.102mA   -10.2mA
600mV     -42.64mA   -26.6mA    -54.61mA
1.2V      -72.81mA   -43.84mA   -94.18mA
1.9V      -93.37mA   -52.9mA    -122.9mA
2.3V      -98.71mA   -54.23mA   -131.7mA
2.8V      -101.3mA   -54.97mA   -136.5mA
5.7V      -107mA     -58mA      -144mA
6.6V      -114mA     -67mA      -152mA
[GND_clamp]
|Voltage   I(typ)   I(min)   I(max)
-3.3V     -9.848A    -9.957A    -9.458A
-1.2V     -3.312A    -4.013A    -2.863A
-1.13V    -2.381A    -3.274A    -1.769A
-1.06V    -1.452A    -2.535A    -684.8mA
-990mV    -542.9mA   -1.798A    -88.04mA
-920mV    -87.13mA   -1.064A    -28.45mA
-850mV    -22.11mA   -382.4mA   -19.62mA
-780mV    -11.98mA   -86.98mA   -13.73mA
-710mV    -7.63mA    -22.27mA   -8.759mA
-640mV    -4.504mA   -7.781mA   -4.831mA
-360mV    -39.8uA    -178.9uA   -19.56uA
3.28V     83.52uA    56.87uA    102.4uA
[POWER_clamp]
|Voltage   I(typ)   I(min)   I(max)
-3.28V    1.355A     1.167A     1.664A
-1.16V    105.7mA    131.6mA    95.69mA
-1.12V    84.97mA    114mA      70.27mA
-1.08V    65.05mA    96.83mA    46.54mA
-1.04V    46.34mA    80.15mA    25.76mA
-1V       29.51mA    64.13mA    10.3mA
-960mV    15.69mA    48.99mA    2.571mA
-920mV    6.373mA    35.1mA     455.6uA
-840mV    490.7uA    13.24mA    11.36uA
-760mV    27.33uA    2.767mA    276.6nA
-640mV    346.6nA    134.1uA    15.48nA
0V        0A         19.91nA    0A
[Ramp]
| variable   typ   min   max
dV/dt_r  1.53198/1.24162n   1.08384/2.76975n   1.76610/0.75458n
dV/dt_f  1.52117/0.97076n   1.01862/2.52687n   1.77922/0.63338n
R_load = 50.000000
[Rising Waveform]
R_fixture= 50.000000
V_fixture= 3.300000
V_fixture_min= 2.700000
V_fixture_max= 3.600000
|time   V(typ)   V(min)   V(max)
0s        764mV      1.001V     633.8mV
985ps     760.7mV    1.001V     791.4mV
1.093ns   772.9mV    1.001V     1.258V
1.321ns   923.5mV    1.001V     3.28V
1.453ns   1.329V     999.7mV    3.555V
1.706ns   2.919V     998.6mV    3.587V
1.898ns   3.249V     1.014V     3.591V
2.342ns   3.29V      1.282V     3.594V
2.955ns   3.294V     2.635V     3.595V
5.982ns   3.299V     2.699V     3.599V
[Rising Waveform]
R_fixture= 50.000000
V_fixture= 0.0
V_fixture_min= 0.0
V_fixture_max= 0.0
|time   V(typ)   V(min)   V(max)
0s        32.79uV    27.42uV    26.75uV
1.141ns   -10.23mV   82.2uV     77.7mV
1.261ns   -10.23mV   130.3uV    236.3mV
1.622ns   77.98mV    -1.37mV    1.182V
2.282ns   914.8mV    -9.747mV   2.535V
3.363ns   2.14V      225.7mV    2.862V
4.204ns   2.392V     576.9mV    2.912V
6.186ns   2.522V     1.367V     2.939V
8.408ns   2.548V     1.69V      2.943V
29.91ns   2.553V     1.806V     2.943V
[Falling Waveform]
R_fixture= 50.000000
V_fixture= 3.300000
V_fixture_min= 2.700000
V_fixture_max= 3.600000
|time   V(typ)   V(min)   V(max)
0s        3.299V     2.699V     3.599V
1.201ns   3.301V     2.705V     3.383V
1.502ns   3.221V     2.705V     2.993V
1.802ns   3.078V     2.705V     2.156V
2.282ns   2.507V     2.698V     959.8mV
3.003ns   1.361V     2.61V      729.8mV
3.784ns   976.6mV    2.367V     678.4mV
6.006ns   813.7mV    1.406V     641.5mV
8.228ns   780.3mV    1.152V     635.6mV
29.91ns   764mV      1.001V     633.8mV
[Falling Waveform]
R_fixture= 50.000000
V_fixture= 0.0
V_fixture_min= 0.0
V_fixture_max= 0.0
|time   V(typ)   V(min)   V(max)
0s        2.553V     1.806V     2.943V
528.5ps   2.497V     1.808V     2.842V
840.8ps   2.356V     1.783V     2.589V
1.069ns   2.19V      1.719V     2.074V
1.526ns   1.39V      1.519V     443.6mV
1.826ns   714.8mV    1.303V     105.6mV
2.054ns   302.2mV    1.11V      28.97mV
2.354ns   89.89mV    857mV      3.319mV
3.483ns   1.453mV    119.4mV    829.9uV
5.982ns   32.79uV    27.42uV    26.75uV
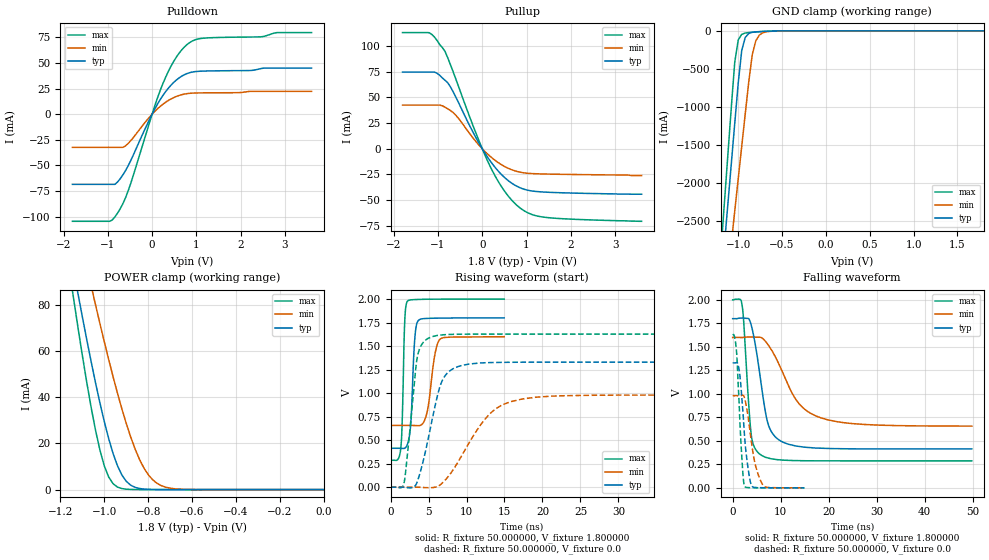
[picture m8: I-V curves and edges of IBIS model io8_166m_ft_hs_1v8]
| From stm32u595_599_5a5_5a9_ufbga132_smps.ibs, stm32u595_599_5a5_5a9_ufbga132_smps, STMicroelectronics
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|   Model io8_166m_ft_hs_1v8
[Model]  io8_166m_ft_hs_1v8
Model_type I/O
Polarity   Non-Inverting
Enable   Active-Low
Vinl =   0.540000V
Vinh =   1.260000V
Vmeas =  0.900000V
Cref =   50.000000pF
Rref =   100.000000M
Vref =   0.0V
C_comp   3.358200pF   3.352700pF   3.400300pF
[Temperature Range]   25.000000   0.140000k   -40.000000
[Pullup Reference]   1.800000V   1.600000V   2.000000V
[Pulldown Reference]   0.0V   0.0V   0.0V
[POWER Clamp Reference]   1.800000V   1.600000V   2.000000V
[GND Clamp Reference]   0.0V   0.0V   0.0V
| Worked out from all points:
|   slope of the pulldown table from 0 to 0.27 V, typ, clamps not added: 13.6 ohm
|   slope of the pullup table from 0 to 0.27 V, typ, clamps not added: 15.9 ohm
|   GND clamp passes 1 mA (typ) near -0.51 V on its own axis
|   POWER clamp passes 1 mA (typ) near -0.86 V on its own axis
|   rising waveform, R_fixture 50.000000, V_fixture 1.800000: 20-80 % time 469ps typ, 911ps min, 313ps max; typ from 0.414 V to 1.8 V
|   rising waveform, R_fixture 50.000000, V_fixture 0.0: 20-80 % time 2.22ns typ, 4.8ns min, 1.18ns max; typ from 0 V to 1.33 V
|   falling waveform, R_fixture 50.000000, V_fixture 1.800000: 20-80 % time 2.6ns typ, 6.1ns min, 1.3ns max; typ from 1.8 V to 0.414 V
|   falling waveform, R_fixture 50.000000, V_fixture 0.0: 20-80 % time 1.31ns typ, 1.86ns min, 937ps max; typ from 1.33 V to 0 V
[Pulldown]
|Voltage   I(typ)   I(min)   I(max)
-1.8V     -68.38mA   -32.32mA   -104.4mA
-960mV    -68.38mA   -32.32mA   -104.4mA
-780mV    -66.08mA   -32.32mA   -96.42mA
-660mV    -59.2mA    -32.31mA   -87.22mA
-540mV    -50.22mA   -28.51mA   -74.66mA
0V        0A         -200fA     0A
240mV     18.04mA    9.6mA      29.42mA
480mV     30.68mA    16.02mA    50.95mA
780mV     39.48mA    19.99mA    67.57mA
1.14V     41.99mA    20.78mA    74.01mA
2.82V     44.93mA    22.28mA    79.57mA
3.6V      44.93mA    22.28mA    79.57mA
[Pullup]
|Voltage   I(typ)   I(min)   I(max)
-1.8V     74.48mA    42.39mA    112.9mA
-1.2V     74.48mA    42.39mA    112.8mA
-1.02V    73.36mA    42.39mA    105.2mA
-840mV    66.55mA    40.38mA    94.54mA
-600mV    50.53mA    32.7mA     68.14mA
-180mV    13.77mA    8.913mA    19.32mA
180mV     -11.9mA    -7.442mA   -17.26mA
480mV     -26.98mA   -16.65mA   -39.76mA
840mV     -37.65mA   -22.63mA   -57.07mA
1.08V     -40.74mA   -24.01mA   -63.22mA
1.44V     -42.19mA   -24.58mA   -66.73mA
3.6V      -44.2mA    -26mA      -70.5mA
[GND_clamp]
|Voltage   I(typ)   I(min)   I(max)
-1.8V     -9.908A    -9.683A    -9.994A
-1.2V     -3.383A    -4.084A    -2.934A
-1.16V    -2.841A    -3.655A    -2.294A
-1.12V    -2.299A    -3.226A    -1.656A
-1.04V    -1.218A    -2.369A    -414.2mA
-1V       -684.7mA   -1.941A    -119.2mA
-960mV    -257.2mA   -1.514A    -45.66mA
-920mV    -87.03mA   -1.089A    -28.93mA
-840mV    -19.35mA   -312.8mA   -18.97mA
-800mV    -13.55mA   -132.4mA   -15.49mA
-720mV    -8.042mA   -25.67mA   -9.491mA
1.8V      0A         13.64nA    0A
[POWER_clamp]
|Voltage   I(typ)   I(min)   I(max)
-1.8V     470.8mA    433.7mA    554.6mA
-1.14V    95.25mA    122.7mA    82.82mA
-1.12V    84.97mA    114mA      70.27mA
-1.06V    55.51mA    88.42mA    35.67mA
-1.04V    46.34mA    80.15mA    25.76mA
-1V       29.51mA    64.13mA    10.3mA
-940mV    10.39mA    41.86mA    1.109mA
-900mV    3.624mA    28.77mA    182.8uA
-840mV    490.7uA    13.24mA    11.35uA
-800mV    116.8uA    6.532mA    1.77uA
-740mV    13.2uA     1.724mA    109.3nA
0V        0A         18.75nA    0A
[Ramp]
| variable   typ   min   max
dV/dt_r  0.79770/2.21630n   0.58815/4.79330n   0.97668/1.17756n
dV/dt_f  0.83164/2.59665n   0.56566/6.09696n   1.02770/1.29890n
R_load = 50.000000
[Rising Waveform]
R_fixture= 50.000000
V_fixture= 1.800000
V_fixture_min= 1.600000
V_fixture_max= 2.000000
|time   V(typ)   V(min)   V(max)
0s        413.9mV    656.8mV    287.2mV
1.351ns   413.5mV    656.9mV    419.7mV
1.862ns   414.6mV    656.9mV    1.758V
2.192ns   451.2mV    656.9mV    1.975V
2.613ns   632mV      656.8mV    1.992V
3.153ns   1.541V     656.1mV    1.995V
3.604ns   1.767V     654.6mV    1.996V
4.805ns   1.795V     796.6mV    1.999V
6.426ns   1.798V     1.566V     2V
14.95ns   1.8V       1.6V       2V
[Rising Waveform]
R_fixture= 50.000000
V_fixture= 0.0
V_fixture_min= 0.0
V_fixture_max= 0.0
|time   V(typ)   V(min)   V(max)
0s        1.723uV    2.333uV    145nV
1.802ns   -1.129mV   22.95nV    55.07mV
3.504ns   56.2mV     15.55uV    1.376V
4.104ns   219mV      -2.326mV   1.517V
5.005ns   535.2mV    -5.356mV   1.585V
6.807ns   1.134V     44.6mV     1.619V
9.51ns    1.297V     356mV      1.627V
13.11ns   1.325V     783.2mV    1.628V
17.32ns   1.329V     937.9mV    1.628V
49.85ns   1.33V      980.3mV    1.628V
[Falling Waveform]
R_fixture= 50.000000
V_fixture= 1.800000
V_fixture_min= 1.600000
V_fixture_max= 2.000000
|time   V(typ)   V(min)   V(max)
0s        1.8V       1.6V       2V
1.902ns   1.806V     1.6V       1.961V
2.302ns   1.806V     1.601V     1.769V
3.904ns   1.726V     1.605V     553.4mV
6.206ns   1.01V      1.591V     339.9mV
7.307ns   694.2mV    1.528V     319mV
8.809ns   547mV      1.403V     303.6mV
13.31ns   444.3mV    930.5mV    289.9mV
17.82ns   422.9mV    755.7mV    287.6mV
49.85ns   413.9mV    656.8mV    287.2mV
[Falling Waveform]
R_fixture= 50.000000
V_fixture= 0.0
V_fixture_min= 0.0
V_fixture_max= 0.0
|time   V(typ)   V(min)   V(max)
0s        1.33V      980.3mV    1.628V
720.7ps   1.332V     980.3mV    1.499V
1.381ns   1.244V     980.2mV    857.5mV
2.072ns   856.7mV    986.2mV    198.9mV
2.492ns   541.3mV    952.4mV    16.56mV
3.123ns   242.6mV    787.4mV    3.204mV
3.844ns   36.14mV    512.6mV    1.607mV
4.715ns   4.417mV    247mV      952.9uV
6.126ns   1.46mV     45mV       557uV
14.95ns   1.723uV    2.333uV    145nV
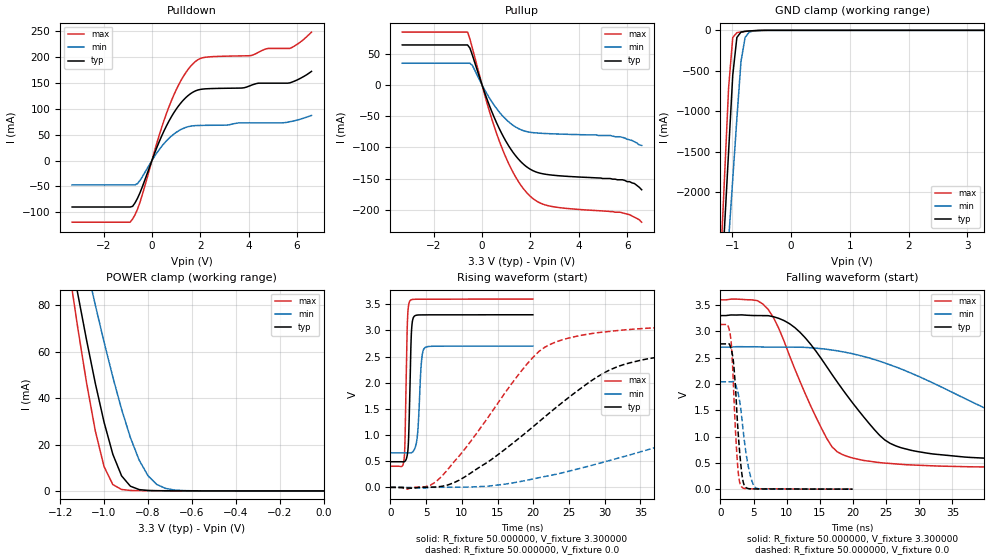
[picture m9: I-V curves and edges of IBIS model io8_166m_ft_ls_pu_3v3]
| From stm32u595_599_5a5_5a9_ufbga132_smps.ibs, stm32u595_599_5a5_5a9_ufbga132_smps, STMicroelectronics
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|   Model io8_166m_ft_ls_pu_3v3
[Model]  io8_166m_ft_ls_pu_3v3
Model_type I/O
Polarity   Non-Inverting
Enable   Active-Low
Vinl =   0.990000V
Vinh =   2.310000V
Vmeas =  1.650000V
Cref =   50.000000pF
Rref =   100.000000M
Vref =   0.0V
C_comp   3.517100pF   3.489300pF   3.557700pF
[Temperature Range]   25.000000   0.140000k   -40.000000
[Pullup Reference]   3.300000V   2.700000V   3.600000V
[Pulldown Reference]   0.0V   0.0V   0.0V
[POWER Clamp Reference]   3.300000V   2.700000V   3.600000V
[GND Clamp Reference]   0.0V   0.0V   0.0V
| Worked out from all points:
|   slope of the pulldown table from 0 to 0.495 V, typ, clamps not added: 8.73 ohm
|   slope of the pullup table from 0 to 0.495 V, typ, clamps not added: 9.64 ohm
|   GND clamp passes 1 mA (typ) near -0.50 V on its own axis
|   POWER clamp passes 1 mA (typ) near -0.85 V on its own axis
|   rising waveform, R_fixture 50.000000, V_fixture 3.300000: 20-80 % time 307ps typ, 454ps min, 271ps max; typ from 0.49 V to 3.3 V
|   rising waveform, R_fixture 50.000000, V_fixture 0.0: 20-80 % time 15.9ns typ, 34.3ns min, 10.3ns max; typ from 0.001 V to 2.76 V
|   falling waveform, R_fixture 50.000000, V_fixture 3.300000: 20-80 % time 10.1ns typ, 22.3ns min, 6.6ns max; typ from 3.3 V to 0.49 V
|   falling waveform, R_fixture 50.000000, V_fixture 0.0: 20-80 % time 899ps typ, 1.3ns min, 737ps max; typ from 2.76 V to 0.001 V
[Pulldown]
|Voltage   I(typ)   I(min)   I(max)
-3.3V     -89.71mA   -47.06mA   -119mA
-900mV    -89.71mA   -47.06mA   -119mA
-500mV    -62.92mA   -38.72mA   -81.44mA
300mV     36.2mA     21.01mA    48.7mA
800mV     84.07mA    46.96mA    114.8mA
1.3V      116.7mA    62.09mA    162.4mA
1.8V      134.4mA    67.39mA    191.2mA
2.3V      138.6mA    67.98mA    199.8mA
4.1V      145.2mA    72.76mA    202.7mA
4.8V      149.3mA    72.76mA    216.4mA
5.7V      149.8mA    74.9mA     216.4mA
6.6V      172mA      87.1mA     247.9mA
[Pullup]
|Voltage   I(typ)   I(min)   I(max)
-3.3V     64.1mA     34.77mA    84.71mA
-600mV    64.1mA     34.77mA    84.71mA
-400mV    47.78mA    31.25mA    59.05mA
300mV     -32.62mA   -20.62mA   -41.63mA
800mV     -76.87mA   -47.45mA   -98.74mA
1.4V      -114.1mA   -67.68mA   -148.3mA
1.7V      -126.6mA   -73.14mA   -165.8mA
2.1V      -137.3mA   -76.42mA   -182mA
3V        -144.9mA   -78.48mA   -195.5mA
5.8V      -152mA     -84mA      -205mA
6.3V      -158mA     -91mA      -212mA
6.6V      -168mA     -97mA      -220mA
[GND_clamp]
|Voltage   I(typ)   I(min)   I(max)
-3.3V     -9.098A    -9.372A    -9.671A
-1.2V     -3.386A    -4.091A    -2.933A
-1.13V    -2.437A    -3.34A     -1.815A
-1.06V    -1.49A     -2.588A    -705.6mA
-990mV    -555.7mA   -1.839A    -89.03mA
-920mV    -88.12mA   -1.093A    -28.78mA
-850mV    -22.35mA   -387.4mA   -19.84mA
-780mV    -12.12mA   -88.01mA   -13.88mA
-710mV    -7.71mA    -22.52mA   -8.846mA
-640mV    -4.545mA   -7.864mA   -4.87mA
-360mV    -31.12uA   -173.5uA   -8.497uA
3.28V     0A         14.15nA    -7.901nA
[POWER_clamp]
|Voltage   I(typ)   I(min)   I(max)
-3.28V    1.355A     1.167A     1.665A
-1.16V    105.8mA    131.6mA    95.87mA
-1.12V    85.08mA    114mA      70.45mA
-1.08V    65.17mA    96.88mA    46.74mA
-1.04V    46.48mA    80.2mA     25.96mA
-1V       29.63mA    64.18mA    10.49mA
-960mV    15.81mA    49.06mA    2.743mA
-920mV    6.481mA    35.16mA    612.1uA
-840mV    577.5uA    13.29mA    137.6uA
-760mV    93.73uA    2.807mA    97.77uA
-640mV    40.05uA    158.9uA    59.33uA
0V        0A         19.33nA    0A
[Ramp]
| variable   typ   min   max
dV/dt_r  1.65687/15.83458n   1.22436/34.20468n   1.87831/10.28869n
dV/dt_f  1.68571/10.07196n   1.22377/22.26643n   1.91753/6.57021n
R_load = 50.000000
[Rising Waveform]
R_fixture= 50.000000
V_fixture= 3.300000
V_fixture_min= 2.700000
V_fixture_max= 3.600000
|time   V(typ)   V(min)   V(max)
0s        490.5mV    660.4mV    404.1mV
1.922ns   490.2mV    660.4mV    524.7mV
2.042ns   499.1mV    660.4mV    808.6mV
2.402ns   640.8mV    660.1mV    3.183V
2.763ns   1.964V     659.2mV    3.568V
3.123ns   3.195V     677.1mV    3.593V
3.764ns   3.294V     948.2mV    3.597V
4.364ns   3.297V     2.404V     3.597V
4.845ns   3.298V     2.671V     3.597V
19.94ns   3.3V       2.7V       3.6V
[Rising Waveform]
R_fixture= 50.000000
V_fixture= 0.0
V_fixture_min= 0.0
V_fixture_max= 0.0
|time   V(typ)   V(min)   V(max)
0s        557.7uV    595uV      578.3uV
6.406ns   7.608mV    2.275mV    110.4mV
13.61ns   481.6mV    23.01mV    1.327V
18.42ns   984.9mV    117.8mV    2.239V
21.62ns   1.35V      208.7mV    2.68V
30.43ns   2.228V     504.8mV    2.978V
36.04ns   2.458V     720.9mV    3.043V
63.26ns   2.713V     1.658V     3.122V
97.7ns    2.755V     1.946V     3.13V
398.8ns   2.762V     2.041V     3.131V
[Falling Waveform]
R_fixture= 50.000000
V_fixture= 3.300000
V_fixture_min= 2.700000
V_fixture_max= 3.600000
|time   V(typ)   V(min)   V(max)
0s        3.3V       2.7V       3.6V
5.606ns   3.3V       2.707V     3.583V
7.207ns   3.299V     2.701V     3.418V
12.01ns   2.982V     2.699V     2.046V
17.62ns   2.039V     2.631V     711.3mV
24.02ns   1.023V     2.433V     505.2mV
28.03ns   763.1mV    2.245V     465.5mV
49.65ns   541.3mV    1.061V     411.1mV
81.68ns   499.2mV    757.6mV    404.8mV
398.8ns   490.5mV    660.4mV    404.1mV
[Falling Waveform]
R_fixture= 50.000000
V_fixture= 0.0
V_fixture_min= 0.0
V_fixture_max= 0.0
|time   V(typ)   V(min)   V(max)
0s        2.762V     2.041V     3.131V
1.041ns   2.762V     2.041V     3.128V
1.522ns   2.707V     2.041V     2.908V
2.002ns   2.377V     2.044V     1.867V
2.563ns   1.296V     1.883V     514.1mV
2.843ns   797.8mV    1.716V     170.4mV
3.203ns   325.3mV    1.381V     42.9mV
4.244ns   11.4mV     412.4mV    7.665mV
5.325ns   4.777mV    27.66mV    6.931mV
19.94ns   557.7uV    595uV      578.3uV
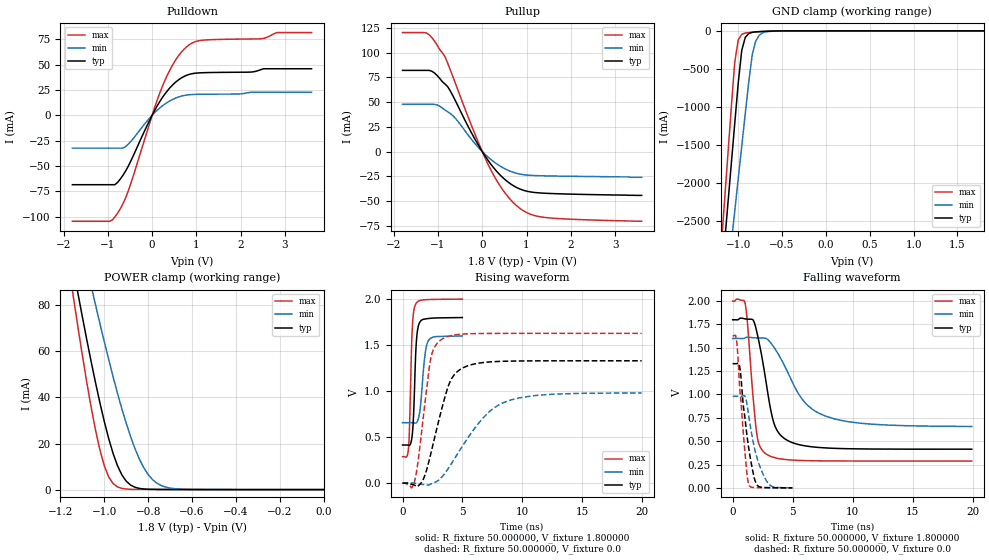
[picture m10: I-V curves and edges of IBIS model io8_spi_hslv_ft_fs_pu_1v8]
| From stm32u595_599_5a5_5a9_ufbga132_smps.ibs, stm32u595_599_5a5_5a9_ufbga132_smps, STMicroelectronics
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|   Model io8_spi_hslv_ft_fs_pu_1v8
[Model]  io8_spi_hslv_ft_fs_pu_1v8
Model_type I/O
Polarity   Non-Inverting
Enable   Active-Low
Vinl =   0.540000V
Vinh =   1.260000V
Vmeas =  0.900000V
Cref =   50.000000pF
Rref =   100.000000M
Vref =   0.0V
C_comp   3.338700pF   3.332500pF   3.379000pF
[Temperature Range]   25.000000   0.140000k   -40.000000
[Pullup Reference]   1.800000V   1.600000V   2.000000V
[Pulldown Reference]   0.0V   0.0V   0.0V
[POWER Clamp Reference]   1.800000V   1.600000V   2.000000V
[GND Clamp Reference]   0.0V   0.0V   0.0V
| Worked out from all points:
|   slope of the pulldown table from 0 to 0.27 V, typ, clamps not added: 13.6 ohm
|   slope of the pullup table from 0 to 0.27 V, typ, clamps not added: 15.9 ohm
|   GND clamp passes 1 mA (typ) near -0.51 V on its own axis
|   POWER clamp passes 1 mA (typ) near -0.86 V on its own axis
|   rising waveform, R_fixture 50.000000, V_fixture 1.800000: 20-80 % time 244ps typ, 387ps min, 217ps max; typ from 0.414 V to 1.8 V
|   rising waveform, R_fixture 50.000000, V_fixture 0.0: 20-80 % time 1.59ns typ, 3.32ns min, 900ps max; typ from 0 V to 1.33 V
|   falling waveform, R_fixture 50.000000, V_fixture 1.800000: 20-80 % time 1.19ns typ, 2.71ns min, 659ps max; typ from 1.8 V to 0.414 V
|   falling waveform, R_fixture 50.000000, V_fixture 0.0: 20-80 % time 778ps typ, 1.04ns min, 580ps max; typ from 1.33 V to 0 V
[Pulldown]
|Voltage   I(typ)   I(min)   I(max)
-1.8V     -68.38mA   -32.32mA   -104.4mA
-960mV    -68.38mA   -32.32mA   -104.4mA
-780mV    -66.07mA   -32.32mA   -96.42mA
-540mV    -50.22mA   -28.51mA   -74.66mA
0V        0A         0A         0A
240mV     18.04mA    9.599mA    29.41mA
480mV     30.68mA    16.02mA    50.95mA
780mV     39.47mA    19.98mA    67.56mA
1.14V     41.98mA    20.78mA    74.01mA
2.46V     45.09mA    22.68mA    75.44mA
2.82V     45.89mA    22.68mA    81.56mA
3.6V      45.89mA    22.68mA    81.56mA
[Pullup]
|Voltage   I(typ)   I(min)   I(max)
-1.8V     82.1mA     47.76mA    120.3mA
-1.26V    82.1mA     47.76mA    120mA
-1.08V    79.5mA     47.76mA    111.9mA
-840mV    68.27mA    42.01mA    95.92mA
-660mV    56.17mA    36.22mA    75.41mA
-240mV    18.69mA    12.2mA     26.01mA
120mV     -8.174mA   -5.123mA   -11.83mA
480mV     -26.98mA   -16.65mA   -39.76mA
840mV     -37.65mA   -22.63mA   -57.07mA
1.08V     -40.74mA   -24.01mA   -63.22mA
1.44V     -42.19mA   -24.58mA   -66.73mA
3.6V      -44.3mA    -26mA      -70.5mA
[GND_clamp]
|Voltage   I(typ)   I(min)   I(max)
-1.8V     -9.908A    -9.683A    -9.994A
-1.2V     -3.383A    -4.084A    -2.934A
-1.16V    -2.841A    -3.655A    -2.294A
-1.12V    -2.299A    -3.226A    -1.656A
-1.04V    -1.218A    -2.369A    -414.2mA
-1V       -684.7mA   -1.941A    -119.2mA
-960mV    -257.2mA   -1.514A    -45.66mA
-920mV    -87.03mA   -1.089A    -28.93mA
-840mV    -19.35mA   -312.8mA   -18.96mA
-800mV    -13.55mA   -132.4mA   -15.49mA
-720mV    -8.042mA   -25.66mA   -9.49mA
1.8V      0A         13.64nA    0A
[POWER_clamp]
|Voltage   I(typ)   I(min)   I(max)
-1.8V     470.9mA    433.7mA    554.6mA
-1.14V    95.28mA    122.7mA    82.88mA
-1.12V    85mA       114mA      70.34mA
-1.06V    55.55mA    88.43mA    35.73mA
-1.04V    46.38mA    80.17mA    25.83mA
-1V       29.54mA    64.14mA    10.37mA
-940mV    10.43mA    41.88mA    1.177mA
-900mV    3.66mA     28.79mA    250.5uA
-840mV    527.2uA    13.26mA    95.94uA
-800mV    154uA      6.55mA     88.41uA
-740mV    59.83uA    1.741mA    70.38uA
0V        0A         18.18nA    0A
[Ramp]
| variable   typ   min   max
dV/dt_r  0.79756/1.58375n   0.58770/3.31093n   0.97651/0.89829n
dV/dt_f  0.83131/1.18839n   0.56441/2.70553n   1.02742/0.65777n
R_load = 50.000000
[Rising Waveform]
R_fixture= 50.000000
V_fixture= 1.800000
V_fixture_min= 1.600000
V_fixture_max= 2.000000
|time   V(typ)   V(min)   V(max)
0s        414.5mV    657.5mV    287.7mV
500.5ps   410.4mV    657.7mV    383.1mV
570.6ps   410.2mV    657.7mV    562.6mV
800.8ps   514.7mV    657.4mV    1.652V
920.9ps   743.5mV    655.5mV    1.858V
1.041ns   1.206V     652.4mV    1.93V
1.161ns   1.551V     656.4mV    1.96V
1.311ns   1.704V     696.1mV    1.977V
2.122ns   1.789V     1.541V     1.995V
4.985ns   1.8V       1.6V       2V
[Rising Waveform]
R_fixture= 50.000000
V_fixture= 0.0
V_fixture_min= 0.0
V_fixture_max= 0.0
|time   V(typ)   V(min)   V(max)
0s        414.4uV    507.5uV    391.3uV
1.001ns   -22.06mV   -77.54uV   19.23mV
1.642ns   19.89mV    -13.54mV   614.8mV
2.322ns   301.4mV    -11.54mV   1.336V
3.283ns   814.3mV    67.44mV    1.565V
3.964ns   1.103V     189.7mV    1.601V
4.645ns   1.221V     330.5mV    1.616V
6.647ns   1.31V      698mV      1.627V
8.328ns   1.324V     869.6mV    1.628V
19.94ns   1.33V      980.7mV    1.628V
[Falling Waveform]
R_fixture= 50.000000
V_fixture= 1.800000
V_fixture_min= 1.600000
V_fixture_max= 2.000000
|time   V(typ)   V(min)   V(max)
0s        1.8V       1.6V       2V
1.041ns   1.809V     1.606V     1.975V
1.682ns   1.8V       1.608V     1.004V
2.002ns   1.677V     1.605V     586.7mV
2.803ns   1.119V     1.599V     362.3mV
3.363ns   728.1mV    1.52V      328.8mV
4.004ns   563.4mV    1.387V     310.4mV
5.806ns   455.6mV    948.3mV    293mV
7.728ns   428.1mV    769.2mV    289mV
19.94ns   414.5mV    657.5mV    287.7mV
[Falling Waveform]
R_fixture= 50.000000
V_fixture= 0.0
V_fixture_min= 0.0
V_fixture_max= 0.0
|time   V(typ)   V(min)   V(max)
0s        1.33V      980.7mV    1.628V
320.3ps   1.33V      980.8mV    1.581V
430.4ps   1.336V     980.8mV    1.424V
580.6ps   1.301V     980.7mV    1.081V
1.041ns   731.1mV    977.1mV    357.6mV
1.191ns   564.2mV    896.9mV    151.5mV
1.341ns   424.5mV    770.6mV    38.99mV
1.922ns   57.85mV    372mV      3.413mV
2.803ns   3.49mV     78.59mV    1.452mV
4.985ns   414.4uV    507.5uV    391.3uV
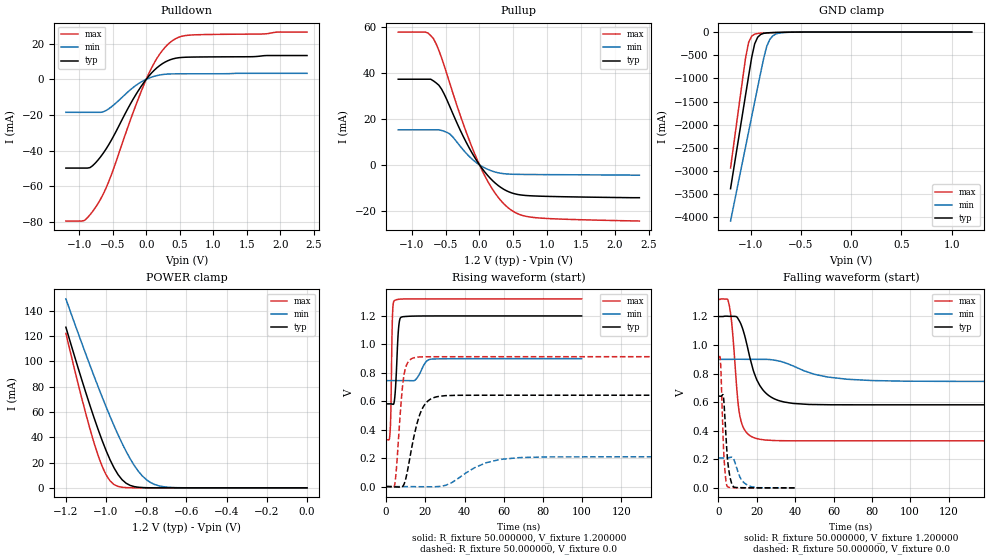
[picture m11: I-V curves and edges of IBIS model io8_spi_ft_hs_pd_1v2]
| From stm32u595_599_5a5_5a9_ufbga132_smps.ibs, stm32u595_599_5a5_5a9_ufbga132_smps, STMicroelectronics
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|   Model io8_spi_ft_hs_pd_1v2
[Model]  io8_spi_ft_hs_pd_1v2
Model_type I/O
Polarity   Non-Inverting
Enable   Active-Low
Vinl =   0.360000V
Vinh =   0.840000V
Vmeas =  0.600000V
Cref =   50.000000pF
Rref =   100.000000M
Vref =   0.0V
C_comp   3.132800pF   3.069700pF   3.178000pF
[Temperature Range]   25.000000   0.140000k   -40.000000
[Pullup Reference]   1.200000V   0.900000V   1.320000V
[Pulldown Reference]   0.0V   0.0V   0.0V
[POWER Clamp Reference]   1.200000V   0.900000V   1.320000V
[GND Clamp Reference]   0.0V   0.0V   0.0V
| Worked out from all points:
|   slope of the pulldown table from 0 to 0.18 V, typ, clamps not added: 25.4 ohm
|   slope of the pullup table from 0 to 0.18 V, typ, clamps not added: 27.8 ohm
|   GND clamp passes 1 mA (typ) near -0.51 V on its own axis
|   POWER clamp passes 1 mA (typ) near -0.86 V on its own axis
|   rising waveform, R_fixture 50.000000, V_fixture 1.200000: 20-80 % time 1.31ns typ, 3.48ns min, 671ps max; typ from 0.581 V to 1.2 V
|   rising waveform, R_fixture 50.000000, V_fixture 0.0: 20-80 % time 6.23ns typ, 15.9ns min, 3.02ns max; typ from 0 V to 0.642 V
|   falling waveform, R_fixture 50.000000, V_fixture 1.200000: 20-80 % time 8.69ns typ, 20.8ns min, 3.71ns max; typ from 1.2 V to 0.581 V
|   falling waveform, R_fixture 50.000000, V_fixture 0.0: 20-80 % time 2.1ns typ, 4.02ns min, 1.52ns max; typ from 0.642 V to 0 V
[Pulldown]
|Voltage   I(typ)   I(min)   I(max)
-1.2V     -49.85mA   -18.57mA   -79.56mA
-920mV    -49.85mA   -18.57mA   -79.19mA
-840mV    -49.59mA   -18.57mA   -76.08mA
-720mV    -45.32mA   -18.57mA   -69.74mA
-560mV    -36.71mA   -16.58mA   -57.44mA
-200mV    -11.43mA   -4.74mA    -19.03mA
0V        -10fA      -700fA     0A
160mV     6.476mA    2.075mA    11.78mA
360mV     10.99mA    2.989mA    20.81mA
480mV     12.07mA    3.053mA    23.52mA
640mV     12.42mA    3.074mA    24.76mA
2.4V      13.31mA    3.34mA     26.51mA
[Pullup]
|Voltage   I(typ)   I(min)   I(max)
-1.2V     37.31mA    15.26mA    57.86mA
-800mV    37.31mA    15.26mA    57.86mA
-680mV    36.58mA    15.26mA    54.98mA
-560mV    33mA       15mA       46.63mA
-440mV    25.52mA    13.49mA    35.67mA
-200mV    10.05mA    5.175mA    14.59mA
0V        0A         0A         0A
200mV     -7.072mA   -2.851mA   -11mA
440mV     -11.84mA   -4.03mA    -19.1mA
600mV     -13.07mA   -4.154mA   -21.71mA
840mV     -13.59mA   -4.223mA   -23.04mA
2.36V     -14.3mA    -4.5mA     -24.46mA
[GND_clamp]
|Voltage   I(typ)   I(min)   I(max)
-1.2V     -3.379A    -4.076A    -2.932A
-1.05V    -1.35A     -2.47A     -550.7mA
-1.02V    -947.8mA   -2.15A     -221.5mA
-990mV    -552.4mA   -1.829A    -88.45mA
-960mV    -255.3mA   -1.51A     -44.89mA
-930mV    -111.8mA   -1.191A    -30.69mA
-870mV    -28.36mA   -564.6mA   -21.36mA
-840mV    -18.66mA   -309.5mA   -18.51mA
-810mV    -14.08mA   -161.6mA   -15.94mA
-780mV    -11.38mA   -83.33mA   -13.55mA
-600mV    -3.019mA   -4.329mA   -3.104mA
1.2V      30.28uA    18.17uA    37.27uA
[POWER_clamp]
|Voltage   I(typ)   I(min)   I(max)
-1.2V     127mA      149.4mA    122.2mA
-1.12V    84.97mA    114mA      70.27mA
-1.06V    55.51mA    88.42mA    35.67mA
-1.02V    37.63mA    72.04mA    17.17mA
-1V       29.51mA    64.13mA    10.3mA
-960mV    15.69mA    48.99mA    2.571mA
-900mV    3.624mA    28.77mA    182.8uA
-840mV    490.7uA    13.24mA    11.35uA
-800mV    116.8uA    6.532mA    1.77uA
-740mV    13.2uA     1.724mA    109.1nA
-620mV    167.4nA    79.36uA    0A
0V        0A         17.87nA    0A
[Ramp]
| variable   typ   min   max
dV/dt_r  0.38525/6.22138n   0.12541/15.90986n   0.54788/3.00489n
dV/dt_f  0.37090/8.68231n   92.60400m/20.76192n 0.59416/3.70415n
R_load = 50.000000
[Rising Waveform]
R_fixture= 50.000000
V_fixture= 1.200000
V_fixture_min= 0.900000
V_fixture_max= 1.320000
|time   V(typ)   V(min)   V(max)
0s        581.3mV    745.2mV    329.2mV
2.002ns   581.4mV    745.2mV    379.9mV
2.402ns   581.3mV    745.2mV    525mV
3.203ns   579.3mV    745.2mV    1.193V
4.204ns   603.2mV    745.2mV    1.307V
6.206ns   1.091V     745.2mV    1.316V
7.608ns   1.19V      745.2mV    1.318V
14.81ns   1.199V     749.3mV    1.319V
23.02ns   1.199V     895.7mV    1.319V
99.7ns    1.2V       899.5mV    1.319V
[Rising Waveform]
R_fixture= 50.000000
V_fixture= 0.0
V_fixture_min= 0.0
V_fixture_max= 0.0
|time   V(typ)   V(min)   V(max)
0s        1.319uV    945.2nV    109.7nV
4.404ns   -1.864mV   781nV      16.67mV
8.809ns   8.011mV    -254.7nV   758.7mV
10.81ns   106mV      8.798uV    866.4mV
14.01ns   342.3mV    -141.9uV   904.6mV
19.22ns   567.1mV    -1.182mV   912.1mV
27.23ns   634.8mV    1.157mV    912.8mV
50.85ns   642.1mV    166.6mV    912.8mV
67.67ns   642.1mV    203.4mV    912.9mV
199.4ns   642.1mV    209.1mV    912.9mV
[Falling Waveform]
R_fixture= 50.000000
V_fixture= 1.200000
V_fixture_min= 0.900000
V_fixture_max= 1.320000
|time   V(typ)   V(min)   V(max)
0s        1.2V       899.5mV    1.319V
5.205ns   1.201V     899.5mV    1.302V
6.807ns   1.201V     899.5mV    1.166V
10.01ns   1.189V     900.6mV    620.8mV
11.21ns   1.161V     900.5mV    499.1mV
18.82ns   797.1mV    899.8mV    349.7mV
26.03ns   648.4mV    898.9mV    333.7mV
38.84ns   591.2mV    854.2mV    329.4mV
80.08ns   581.3mV    751.3mV    329.2mV
199.4ns   581.3mV    745.2mV    329.2mV
[Falling Waveform]
R_fixture= 50.000000
V_fixture= 0.0
V_fixture_min= 0.0
V_fixture_max= 0.0
|time   V(typ)   V(min)   V(max)
0s        642.1mV    209.1mV    912.9mV
1.121ns   641.7mV    209.1mV    869mV
2.563ns   640.3mV    209.1mV    296.4mV
3.524ns   452.7mV    208.9mV    95.55mV
4.484ns   238.3mV    208.9mV    12.25mV
6.166ns   65.29mV    213.4mV    2.454mV
7.848ns   6.258mV    203.2mV    1.018mV
11.61ns   1.293mV    64.32mV    311.9uV
15.62ns   495.8uV    15.91mV    126.8uV
39.88ns   1.319uV    945.2nV    109.7nV
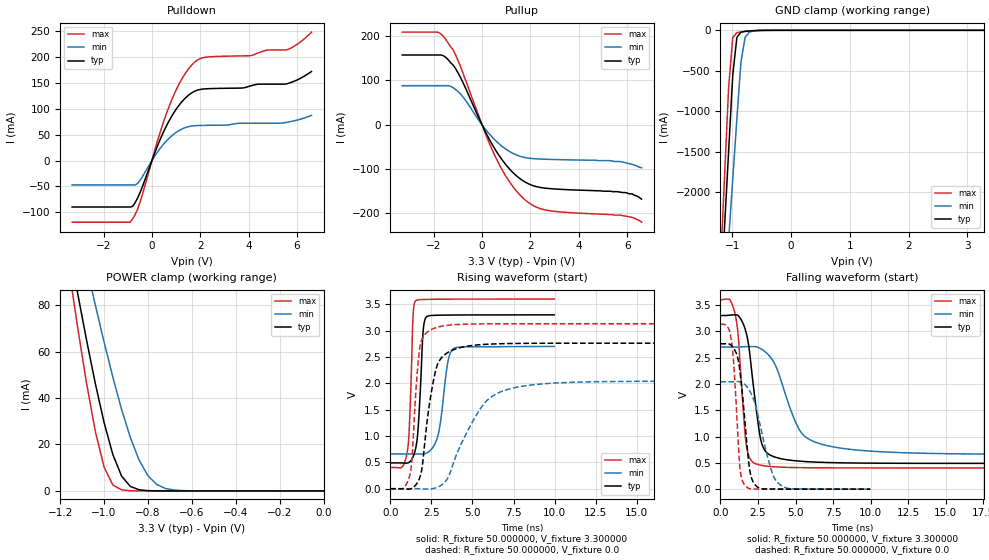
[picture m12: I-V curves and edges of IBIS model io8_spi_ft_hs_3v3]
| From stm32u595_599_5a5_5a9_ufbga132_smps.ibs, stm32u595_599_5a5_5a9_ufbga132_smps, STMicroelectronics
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|   Model io8_spi_ft_hs_3v3
[Model]  io8_spi_ft_hs_3v3
Model_type I/O
Polarity   Non-Inverting
Enable   Active-Low
Vinl =   0.990000V
Vinh =   2.310000V
Vmeas =  1.650000V
Cref =   50.000000pF
Rref =   100.000000M
Vref =   0.0V
C_comp   3.495300pF   3.468500pF   3.534700pF
[Temperature Range]   25.000000   0.140000k   -40.000000
[Pullup Reference]   3.300000V   2.700000V   3.600000V
[Pulldown Reference]   0.0V   0.0V   0.0V
[POWER Clamp Reference]   3.300000V   2.700000V   3.600000V
[GND Clamp Reference]   0.0V   0.0V   0.0V
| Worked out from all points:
|   slope of the pulldown table from 0 to 0.495 V, typ, clamps not added: 8.73 ohm
|   slope of the pullup table from 0 to 0.495 V, typ, clamps not added: 9.64 ohm
|   GND clamp passes 1 mA (typ) near -0.50 V on its own axis
|   POWER clamp passes 1 mA (typ) near -0.85 V on its own axis
|   rising waveform, R_fixture 50.000000, V_fixture 3.300000: 20-80 % time 281ps typ, 498ps min, 209ps max; typ from 0.49 V to 3.3 V
|   rising waveform, R_fixture 50.000000, V_fixture 0.0: 20-80 % time 741ps typ, 2ns min, 395ps max; typ from 0 V to 2.76 V
|   falling waveform, R_fixture 50.000000, V_fixture 3.300000: 20-80 % time 735ps typ, 1.65ns min, 475ps max; typ from 3.3 V to 0.49 V
|   falling waveform, R_fixture 50.000000, V_fixture 0.0: 20-80 % time 556ps typ, 1.05ns min, 388ps max; typ from 2.76 V to 0 V
[Pulldown]
|Voltage   I(typ)   I(min)   I(max)
-3.3V     -89.71mA   -47.06mA   -119mA
-900mV    -89.71mA   -47.06mA   -119mA
-700mV    -81.75mA   -47.06mA   -104.8mA
-500mV    -62.92mA   -38.71mA   -81.44mA
300mV     36.2mA     21.01mA    48.7mA
800mV     84.06mA    46.96mA    114.8mA
1.3V      116.7mA    62.08mA    162.3mA
1.8V      134.4mA    67.38mA    191.2mA
2.2V      138.3mA    67.91mA    199.2mA
4.1V      144.4mA    71.97mA    202.7mA
5.6V      148.4mA    73.95mA    213.9mA
6.6V      171.9mA    87.1mA     247.9mA
[Pullup]
|Voltage   I(typ)   I(min)   I(max)
-3.3V     157.6mA    88.28mA    209.3mA
-1.8V     157.6mA    88.28mA    208.8mA
-1.5V     152.3mA    88.28mA    192.7mA
-1.2V     135.1mA    83.91mA    169.9mA
-900mV    107.7mA    70.22mA    132.8mA
100mV     -11.39mA   -7.258mA   -14.51mA
600mV     -60.65mA   -37.83mA   -77.69mA
1.2V      -103.6mA   -62.35mA   -134mA
1.8V      -129.9mA   -74.33mA   -170.6mA
2.7V      -143.6mA   -78mA      -193.3mA
5.6V      -151mA     -83mA      -204mA
6.6V      -168mA     -97mA      -220mA
[GND_clamp]
|Voltage   I(typ)   I(min)   I(max)
-3.3V     -9.098A    -9.372A    -9.671A
-1.2V     -3.386A    -4.091A    -2.933A
-1.13V    -2.437A    -3.34A     -1.815A
-1.06V    -1.49A     -2.588A    -705.6mA
-990mV    -555.7mA   -1.839A    -89.03mA
-920mV    -88.12mA   -1.093A    -28.78mA
-850mV    -22.35mA   -387.4mA   -19.84mA
-780mV    -12.12mA   -88mA      -13.87mA
-710mV    -7.709mA   -22.52mA   -8.846mA
-640mV    -4.545mA   -7.864mA   -4.87mA
-360mV    -31.12uA   -173.5uA   -8.496uA
3.28V     0A         14.15nA    -7.901nA
[POWER_clamp]
|Voltage   I(typ)   I(min)   I(max)
-3.28V    1.355A     1.167A     1.664A
-1.16V    105.7mA    131.6mA    95.69mA
-1.12V    84.97mA    114mA      70.27mA
-1.08V    65.05mA    96.83mA    46.54mA
-1.04V    46.34mA    80.15mA    25.76mA
-1V       29.51mA    64.13mA    10.3mA
-960mV    15.69mA    48.99mA    2.571mA
-920mV    6.373mA    35.1mA     455.6uA
-840mV    490.7uA    13.24mA    11.36uA
-760mV    27.33uA    2.767mA    279.3nA
-640mV    348nA      134.1uA    17.47nA
0V        0A         19.95nA    0A
[Ramp]
| variable   typ   min   max
dV/dt_r  1.65714/0.73882n   1.22454/1.99571n   1.87854/0.39250n
dV/dt_f  1.68605/0.73211n   1.22336/1.64315n   1.91788/0.47319n
R_load = 50.000000
[Rising Waveform]
R_fixture= 50.000000
V_fixture= 3.300000
V_fixture_min= 2.700000
V_fixture_max= 3.600000
|time   V(typ)   V(min)   V(max)
0s        489.9mV    659.8mV    403.6mV
1.041ns   487.9mV    659.8mV    715.2mV
1.181ns   508.6mV    659.8mV    1.327V
1.381ns   601.5mV    659.7mV    3.257V
1.542ns   761.4mV    659.3mV    3.566V
2.002ns   3.002V     660.2mV    3.591V
2.202ns   3.262V     676.9mV    3.593V
2.943ns   3.293V     1.065V     3.596V
3.844ns   3.296V     2.658V     3.598V
9.97ns    3.3V       2.7V       3.599V
[Rising Waveform]
R_fixture= 50.000000
V_fixture= 0.0
V_fixture_min= 0.0
V_fixture_max= 0.0
|time   V(typ)   V(min)   V(max)
0s        3.014uV    4.632uV    8.805uV
1.201ns   -6.178mV   50.47uV    276.8mV
1.301ns   4.901mV    76.28uV    489.8mV
1.752ns   177.9mV    -815uV     2.582V
2.603ns   2.012V     2.237mV    3.037V
2.953ns   2.411V     39.08mV    3.072V
3.604ns   2.604V     272.7mV    3.105V
5.506ns   2.734V     1.533V     3.128V
7.307ns   2.755V     1.898V     3.131V
24.92ns   2.762V     2.041V     3.131V
[Falling Waveform]
R_fixture= 50.000000
V_fixture= 3.300000
V_fixture_min= 2.700000
V_fixture_max= 3.600000
|time   V(typ)   V(min)   V(max)
0s        3.3V       2.7V       3.599V
1.001ns   3.312V     2.7V       3.295V
1.201ns   3.293V     2.701V     2.865V
1.702ns   2.987V     2.709V     882.4mV
2.302ns   1.708V     2.708V     488mV
2.703ns   918.3mV    2.665V     454.6mV
3.103ns   687.9mV    2.581V     436.8mV
5.255ns   532.6mV    1.128V     409.6mV
6.707ns   510.4mV    856.1mV    405.8mV
24.92ns   489.9mV    659.8mV    403.6mV
[Falling Waveform]
R_fixture= 50.000000
V_fixture= 0.0
V_fixture_min= 0.0
V_fixture_max= 0.0
|time   V(typ)   V(min)   V(max)
0s        2.762V     2.041V     3.131V
740.7ps   2.728V     2.041V     2.801V
920.9ps   2.66V      2.042V     2.238V
1.301ns   2.233V     2.041V     400mV
1.682ns   1.116V     1.974V     56.59mV
1.942ns   379.3mV    1.869V     9.478mV
2.222ns   116.7mV    1.694V     3.323mV
3.403ns   2.502mV    347mV      1.252mV
4.004ns   1.607mV    76.45mV    943.8uV
9.97ns    3.014uV    4.632uV    8.805uV
